VERSION 5.7 ;
  NOWIREEXTENSIONATPIN ON ;
  DIVIDERCHAR "/" ;
  BUSBITCHARS "[]" ;
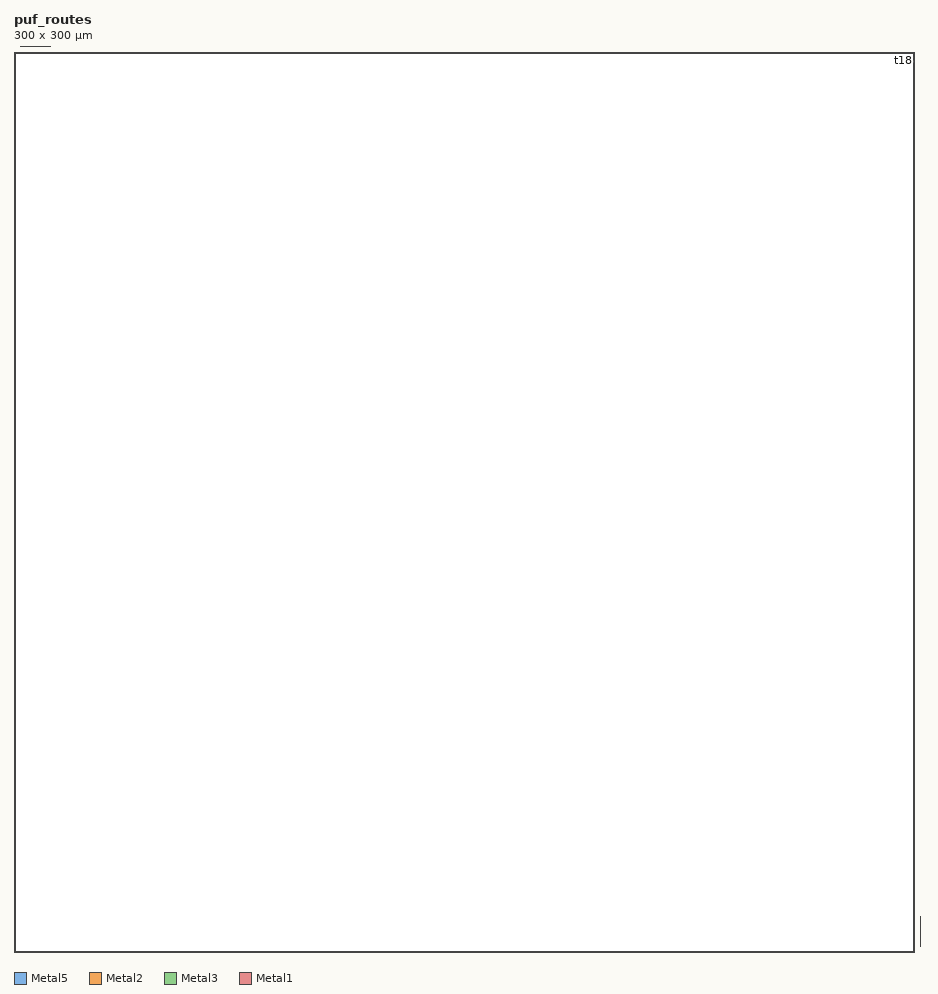
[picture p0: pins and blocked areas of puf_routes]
MACRO puf_routes
  CLASS BLOCK ;
  FOREIGN puf_routes ;
  ORIGIN 0.000 0.000 ;
  SIZE 300.000 BY 300.000 ;
  PIN HI
    DIRECTION INOUT ;
    USE ANALOG ;
    PORT
      LAYER Metal5 ;
        RECT 2.000 724.000 12.000 734.000 ;
      LAYER Metal2 ;
        RECT 330.000 706.860 335.000 751.140 ;
        RECT 331.730 728.130 333.470 729.870 ;
      LAYER Metal3 ;
        RECT 331.730 728.130 333.470 729.870 ;
      LAYER Metal2 ;
        RECT 331.000 728.000 334.000 730.000 ;
      LAYER Metal3 ;
        RECT 331.900 728.000 340.750 730.000 ;
      LAYER Metal1 ;
        RECT 338.700 727.200 342.300 730.800 ;
      LAYER Metal2 ;
        RECT 338.700 727.200 342.300 730.800 ;
        RECT 338.700 727.200 342.300 730.800 ;
      LAYER Metal3 ;
        RECT 338.700 727.200 342.300 730.800 ;
        RECT 338.500 1082.550 636.100 1086.550 ;
      LAYER Metal2 ;
        RECT 632.300 1082.750 635.900 1086.350 ;
      LAYER Metal3 ;
        RECT 632.300 1082.750 635.900 1086.350 ;
      LAYER Metal2 ;
        RECT 634.100 1082.550 637.100 1086.550 ;
      LAYER Metal3 ;
        RECT 338.500 1563.350 716.100 1567.350 ;
      LAYER Metal2 ;
        RECT 712.300 1563.550 715.900 1567.150 ;
      LAYER Metal3 ;
        RECT 712.300 1563.550 715.900 1567.150 ;
      LAYER Metal2 ;
        RECT 714.100 1563.350 717.100 1567.350 ;
      LAYER Metal1 ;
        RECT 338.500 338.500 342.500 1567.350 ;
        RECT 338.500 338.500 3507.500 342.500 ;
      LAYER Metal3 ;
        RECT 3227.900 649.550 3507.500 653.550 ;
      LAYER Metal2 ;
        RECT 3228.100 649.750 3231.700 653.350 ;
      LAYER Metal3 ;
        RECT 3228.100 649.750 3231.700 653.350 ;
      LAYER Metal2 ;
        RECT 3226.900 649.550 3229.900 653.550 ;
      LAYER Metal3 ;
        RECT 3177.900 1098.850 3507.500 1102.850 ;
      LAYER Metal2 ;
        RECT 3178.100 1099.050 3181.700 1102.650 ;
      LAYER Metal3 ;
        RECT 3178.100 1099.050 3181.700 1102.650 ;
      LAYER Metal2 ;
        RECT 3176.900 1098.850 3179.900 1102.850 ;
      LAYER Metal3 ;
        RECT 3237.900 1456.250 3507.500 1460.250 ;
      LAYER Metal2 ;
        RECT 3238.100 1456.450 3241.700 1460.050 ;
      LAYER Metal3 ;
        RECT 3238.100 1456.450 3241.700 1460.050 ;
      LAYER Metal2 ;
        RECT 3236.900 1456.250 3239.900 1460.250 ;
      LAYER Metal3 ;
        RECT 3137.900 1811.250 3507.500 1815.250 ;
      LAYER Metal2 ;
        RECT 3138.100 1811.450 3141.700 1815.050 ;
      LAYER Metal3 ;
        RECT 3138.100 1811.450 3141.700 1815.050 ;
      LAYER Metal2 ;
        RECT 3136.900 1811.250 3139.900 1815.250 ;
      LAYER Metal1 ;
        RECT 3503.500 338.500 3507.500 1815.250 ;
        RECT 338.700 1082.750 342.300 1086.350 ;
      LAYER Metal2 ;
        RECT 338.700 1082.750 342.300 1086.350 ;
        RECT 338.700 1082.750 342.300 1086.350 ;
      LAYER Metal3 ;
        RECT 338.700 1082.750 342.300 1086.350 ;
      LAYER Metal1 ;
        RECT 338.700 1563.550 342.300 1567.150 ;
      LAYER Metal2 ;
        RECT 338.700 1563.550 342.300 1567.150 ;
        RECT 338.700 1563.550 342.300 1567.150 ;
      LAYER Metal3 ;
        RECT 338.700 1563.550 342.300 1567.150 ;
      LAYER Metal1 ;
        RECT 3503.700 649.750 3507.300 653.350 ;
      LAYER Metal2 ;
        RECT 3503.700 649.750 3507.300 653.350 ;
        RECT 3503.700 649.750 3507.300 653.350 ;
      LAYER Metal3 ;
        RECT 3503.700 649.750 3507.300 653.350 ;
      LAYER Metal1 ;
        RECT 3503.700 1099.050 3507.300 1102.650 ;
      LAYER Metal2 ;
        RECT 3503.700 1099.050 3507.300 1102.650 ;
        RECT 3503.700 1099.050 3507.300 1102.650 ;
      LAYER Metal3 ;
        RECT 3503.700 1099.050 3507.300 1102.650 ;
      LAYER Metal1 ;
        RECT 3503.700 1456.450 3507.300 1460.050 ;
      LAYER Metal2 ;
        RECT 3503.700 1456.450 3507.300 1460.050 ;
        RECT 3503.700 1456.450 3507.300 1460.050 ;
      LAYER Metal3 ;
        RECT 3503.700 1456.450 3507.300 1460.050 ;
      LAYER Metal1 ;
        RECT 3503.700 1811.450 3507.300 1815.050 ;
      LAYER Metal2 ;
        RECT 3503.700 1811.450 3507.300 1815.050 ;
        RECT 3503.700 1811.450 3507.300 1815.050 ;
      LAYER Metal3 ;
        RECT 3503.700 1811.450 3507.300 1815.050 ;
    END
  END HI
  PIN LO
    DIRECTION INOUT ;
    USE ANALOG ;
    PORT
      LAYER Metal5 ;
        RECT 2.000 865.000 12.000 875.000 ;
      LAYER Metal2 ;
        RECT 330.000 847.860 335.000 892.140 ;
        RECT 331.730 869.130 333.470 870.870 ;
      LAYER Metal3 ;
        RECT 331.730 869.130 333.470 870.870 ;
      LAYER Metal2 ;
        RECT 331.000 869.000 334.000 871.000 ;
      LAYER Metal3 ;
        RECT 331.900 869.000 345.450 871.000 ;
      LAYER Metal1 ;
        RECT 343.400 868.200 347.000 871.800 ;
      LAYER Metal2 ;
        RECT 343.400 868.200 347.000 871.800 ;
        RECT 343.400 868.200 347.000 871.800 ;
      LAYER Metal3 ;
        RECT 343.400 868.200 347.000 871.800 ;
        RECT 343.200 1087.550 636.100 1091.550 ;
      LAYER Metal2 ;
        RECT 632.300 1087.750 635.900 1091.350 ;
      LAYER Metal3 ;
        RECT 632.300 1087.750 635.900 1091.350 ;
      LAYER Metal2 ;
        RECT 634.100 1087.550 637.100 1091.550 ;
      LAYER Metal3 ;
        RECT 343.200 1568.350 716.100 1572.350 ;
      LAYER Metal2 ;
        RECT 712.300 1568.550 715.900 1572.150 ;
      LAYER Metal3 ;
        RECT 712.300 1568.550 715.900 1572.150 ;
      LAYER Metal2 ;
        RECT 714.100 1568.350 717.100 1572.350 ;
      LAYER Metal1 ;
        RECT 343.200 343.200 347.200 1572.350 ;
        RECT 343.200 343.200 3502.800 347.200 ;
      LAYER Metal3 ;
        RECT 3227.900 654.550 3502.800 658.550 ;
      LAYER Metal2 ;
        RECT 3228.100 654.750 3231.700 658.350 ;
      LAYER Metal3 ;
        RECT 3228.100 654.750 3231.700 658.350 ;
      LAYER Metal2 ;
        RECT 3226.900 654.550 3229.900 658.550 ;
      LAYER Metal3 ;
        RECT 3177.900 1103.850 3502.800 1107.850 ;
      LAYER Metal2 ;
        RECT 3178.100 1104.050 3181.700 1107.650 ;
      LAYER Metal3 ;
        RECT 3178.100 1104.050 3181.700 1107.650 ;
      LAYER Metal2 ;
        RECT 3176.900 1103.850 3179.900 1107.850 ;
      LAYER Metal3 ;
        RECT 3237.900 1461.250 3502.800 1465.250 ;
      LAYER Metal2 ;
        RECT 3238.100 1461.450 3241.700 1465.050 ;
      LAYER Metal3 ;
        RECT 3238.100 1461.450 3241.700 1465.050 ;
      LAYER Metal2 ;
        RECT 3236.900 1461.250 3239.900 1465.250 ;
      LAYER Metal3 ;
        RECT 3432.000 1801.000 3502.800 1805.000 ;
      LAYER Metal2 ;
        RECT 3432.200 1801.200 3435.800 1804.800 ;
      LAYER Metal3 ;
        RECT 3432.200 1801.200 3435.800 1804.800 ;
      LAYER Metal2 ;
        RECT 3432.000 1801.000 3436.000 1820.250 ;
        RECT 3432.200 1816.450 3435.800 1820.050 ;
      LAYER Metal3 ;
        RECT 3432.200 1816.450 3435.800 1820.050 ;
        RECT 3137.900 1816.250 3436.000 1820.250 ;
      LAYER Metal2 ;
        RECT 3138.100 1816.450 3141.700 1820.050 ;
      LAYER Metal3 ;
        RECT 3138.100 1816.450 3141.700 1820.050 ;
      LAYER Metal2 ;
        RECT 3136.900 1816.250 3139.900 1820.250 ;
      LAYER Metal1 ;
        RECT 3498.800 343.200 3502.800 1805.000 ;
        RECT 343.400 1087.750 347.000 1091.350 ;
      LAYER Metal2 ;
        RECT 343.400 1087.750 347.000 1091.350 ;
        RECT 343.400 1087.750 347.000 1091.350 ;
      LAYER Metal3 ;
        RECT 343.400 1087.750 347.000 1091.350 ;
      LAYER Metal1 ;
        RECT 343.400 1568.550 347.000 1572.150 ;
      LAYER Metal2 ;
        RECT 343.400 1568.550 347.000 1572.150 ;
        RECT 343.400 1568.550 347.000 1572.150 ;
      LAYER Metal3 ;
        RECT 343.400 1568.550 347.000 1572.150 ;
      LAYER Metal1 ;
        RECT 3499.000 654.750 3502.600 658.350 ;
      LAYER Metal2 ;
        RECT 3499.000 654.750 3502.600 658.350 ;
        RECT 3499.000 654.750 3502.600 658.350 ;
      LAYER Metal3 ;
        RECT 3499.000 654.750 3502.600 658.350 ;
      LAYER Metal1 ;
        RECT 3499.000 1104.050 3502.600 1107.650 ;
      LAYER Metal2 ;
        RECT 3499.000 1104.050 3502.600 1107.650 ;
        RECT 3499.000 1104.050 3502.600 1107.650 ;
      LAYER Metal3 ;
        RECT 3499.000 1104.050 3502.600 1107.650 ;
      LAYER Metal1 ;
        RECT 3499.000 1461.450 3502.600 1465.050 ;
      LAYER Metal2 ;
        RECT 3499.000 1461.450 3502.600 1465.050 ;
        RECT 3499.000 1461.450 3502.600 1465.050 ;
      LAYER Metal3 ;
        RECT 3499.000 1461.450 3502.600 1465.050 ;
      LAYER Metal1 ;
        RECT 3499.000 1801.200 3502.600 1804.800 ;
      LAYER Metal2 ;
        RECT 3499.000 1801.200 3502.600 1804.800 ;
        RECT 3499.000 1801.200 3502.600 1804.800 ;
      LAYER Metal3 ;
        RECT 3499.000 1801.200 3502.600 1804.800 ;
    END
  END LO
  PIN t0
    DIRECTION INOUT ;
    USE ANALOG ;
    PORT
      LAYER Metal5 ;
        RECT 2.000 1006.000 12.000 1016.000 ;
      LAYER Metal2 ;
        RECT 330.000 988.860 335.000 1033.140 ;
        RECT 331.730 1010.130 333.470 1011.870 ;
      LAYER Metal3 ;
        RECT 331.730 1010.130 333.470 1011.870 ;
      LAYER Metal2 ;
        RECT 331.000 1010.000 334.000 1012.000 ;
      LAYER Metal3 ;
        RECT 331.900 1010.000 351.250 1012.000 ;
      LAYER Metal1 ;
        RECT 350.750 1010.750 351.250 1011.250 ;
      LAYER Metal2 ;
        RECT 350.750 1010.750 351.250 1011.250 ;
        RECT 350.750 1010.750 351.250 1011.250 ;
      LAYER Metal3 ;
        RECT 350.750 1010.750 351.250 1011.250 ;
      LAYER Metal1 ;
        RECT 350.650 1010.650 351.350 1094.000 ;
        RECT 350.750 1093.400 351.250 1093.900 ;
      LAYER Metal2 ;
        RECT 350.750 1093.400 351.250 1093.900 ;
        RECT 350.750 1093.400 351.250 1093.900 ;
      LAYER Metal3 ;
        RECT 350.750 1093.400 351.250 1093.900 ;
        RECT 350.700 1093.350 637.400 1093.950 ;
    END
  END t0
  PIN t1
    DIRECTION INOUT ;
    USE ANALOG ;
    PORT
      LAYER Metal5 ;
        RECT 2.000 1147.000 12.000 1157.000 ;
      LAYER Metal2 ;
        RECT 330.000 1129.860 335.000 1174.140 ;
        RECT 331.730 1151.130 333.470 1152.870 ;
      LAYER Metal3 ;
        RECT 331.730 1151.130 333.470 1152.870 ;
      LAYER Metal2 ;
        RECT 331.000 1151.000 334.000 1153.000 ;
      LAYER Metal3 ;
        RECT 331.900 1151.000 352.550 1153.000 ;
      LAYER Metal1 ;
        RECT 352.050 1151.750 352.550 1152.250 ;
      LAYER Metal2 ;
        RECT 352.050 1151.750 352.550 1152.250 ;
        RECT 352.050 1151.750 352.550 1152.250 ;
      LAYER Metal3 ;
        RECT 352.050 1151.750 352.550 1152.250 ;
      LAYER Metal1 ;
        RECT 351.950 1094.400 352.650 1152.350 ;
        RECT 352.050 1094.500 352.550 1095.000 ;
      LAYER Metal2 ;
        RECT 352.050 1094.500 352.550 1095.000 ;
        RECT 352.050 1094.500 352.550 1095.000 ;
      LAYER Metal3 ;
        RECT 352.050 1094.500 352.550 1095.000 ;
        RECT 352.000 1094.450 637.400 1095.050 ;
    END
  END t1
  PIN t2
    DIRECTION INOUT ;
    USE ANALOG ;
    PORT
      LAYER Metal5 ;
        RECT 2.000 1288.000 12.000 1298.000 ;
      LAYER Metal2 ;
        RECT 330.000 1270.860 335.000 1315.140 ;
        RECT 331.730 1292.130 333.470 1293.870 ;
      LAYER Metal3 ;
        RECT 331.730 1292.130 333.470 1293.870 ;
      LAYER Metal2 ;
        RECT 331.000 1292.000 334.000 1294.000 ;
      LAYER Metal3 ;
        RECT 331.900 1292.000 353.850 1294.000 ;
      LAYER Metal1 ;
        RECT 353.350 1292.750 353.850 1293.250 ;
      LAYER Metal2 ;
        RECT 353.350 1292.750 353.850 1293.250 ;
        RECT 353.350 1292.750 353.850 1293.250 ;
      LAYER Metal3 ;
        RECT 353.350 1292.750 353.850 1293.250 ;
      LAYER Metal1 ;
        RECT 353.250 1095.500 353.950 1293.350 ;
        RECT 353.350 1095.600 353.850 1096.100 ;
      LAYER Metal2 ;
        RECT 353.350 1095.600 353.850 1096.100 ;
        RECT 353.350 1095.600 353.850 1096.100 ;
      LAYER Metal3 ;
        RECT 353.350 1095.600 353.850 1096.100 ;
        RECT 353.300 1095.550 637.400 1096.150 ;
    END
  END t2
  PIN t3
    DIRECTION INOUT ;
    USE ANALOG ;
    PORT
      LAYER Metal5 ;
        RECT 2.000 1429.000 12.000 1439.000 ;
      LAYER Metal2 ;
        RECT 330.000 1411.860 335.000 1456.140 ;
        RECT 331.730 1433.130 333.470 1434.870 ;
      LAYER Metal3 ;
        RECT 331.730 1433.130 333.470 1434.870 ;
      LAYER Metal2 ;
        RECT 331.000 1433.000 334.000 1435.000 ;
      LAYER Metal3 ;
        RECT 331.900 1433.000 355.150 1435.000 ;
      LAYER Metal1 ;
        RECT 354.650 1433.750 355.150 1434.250 ;
      LAYER Metal2 ;
        RECT 354.650 1433.750 355.150 1434.250 ;
        RECT 354.650 1433.750 355.150 1434.250 ;
      LAYER Metal3 ;
        RECT 354.650 1433.750 355.150 1434.250 ;
      LAYER Metal1 ;
        RECT 354.550 1096.600 355.250 1434.350 ;
        RECT 354.650 1096.700 355.150 1097.200 ;
      LAYER Metal2 ;
        RECT 354.650 1096.700 355.150 1097.200 ;
        RECT 354.650 1096.700 355.150 1097.200 ;
      LAYER Metal3 ;
        RECT 354.650 1096.700 355.150 1097.200 ;
        RECT 354.600 1096.650 637.400 1097.250 ;
    END
  END t3
  PIN t4
    DIRECTION INOUT ;
    USE ANALOG ;
    PORT
      LAYER Metal5 ;
        RECT 2.000 1570.000 12.000 1580.000 ;
      LAYER Metal2 ;
        RECT 330.000 1552.860 335.000 1597.140 ;
        RECT 331.730 1574.130 333.470 1575.870 ;
      LAYER Metal3 ;
        RECT 331.730 1574.130 333.470 1575.870 ;
      LAYER Metal2 ;
        RECT 331.000 1574.000 334.000 1576.000 ;
      LAYER Metal3 ;
        RECT 331.900 1574.000 356.450 1576.000 ;
        RECT 355.900 1574.150 717.400 1574.750 ;
    END
  END t4
  PIN t5
    DIRECTION INOUT ;
    USE ANALOG ;
    PORT
      LAYER Metal5 ;
        RECT 2.000 1711.000 12.000 1721.000 ;
      LAYER Metal2 ;
        RECT 330.000 1693.860 335.000 1738.140 ;
        RECT 331.730 1715.130 333.470 1716.870 ;
      LAYER Metal3 ;
        RECT 331.730 1715.130 333.470 1716.870 ;
      LAYER Metal2 ;
        RECT 331.000 1715.000 334.000 1717.000 ;
      LAYER Metal3 ;
        RECT 331.900 1715.000 357.750 1717.000 ;
      LAYER Metal1 ;
        RECT 357.250 1715.750 357.750 1716.250 ;
      LAYER Metal2 ;
        RECT 357.250 1715.750 357.750 1716.250 ;
        RECT 357.250 1715.750 357.750 1716.250 ;
      LAYER Metal3 ;
        RECT 357.250 1715.750 357.750 1716.250 ;
      LAYER Metal1 ;
        RECT 357.150 1575.200 357.850 1716.350 ;
        RECT 357.250 1575.300 357.750 1575.800 ;
      LAYER Metal2 ;
        RECT 357.250 1575.300 357.750 1575.800 ;
        RECT 357.250 1575.300 357.750 1575.800 ;
      LAYER Metal3 ;
        RECT 357.250 1575.300 357.750 1575.800 ;
        RECT 357.200 1575.250 717.400 1575.850 ;
    END
  END t5
  PIN t6
    DIRECTION INOUT ;
    USE ANALOG ;
    PORT
      LAYER Metal5 ;
        RECT 1466.500 2.000 1476.500 12.000 ;
      LAYER Metal2 ;
        RECT 1449.360 330.000 1493.640 335.000 ;
        RECT 1470.500 330.000 1472.500 352.000 ;
      LAYER Metal1 ;
        RECT 1471.250 350.750 1471.750 351.250 ;
      LAYER Metal2 ;
        RECT 1471.250 350.750 1471.750 351.250 ;
      LAYER Metal1 ;
        RECT 358.450 350.650 1471.850 351.350 ;
        RECT 358.450 350.650 359.150 1098.400 ;
        RECT 358.550 1097.800 359.050 1098.300 ;
      LAYER Metal2 ;
        RECT 358.550 1097.800 359.050 1098.300 ;
        RECT 358.550 1097.800 359.050 1098.300 ;
      LAYER Metal3 ;
        RECT 358.550 1097.800 359.050 1098.300 ;
        RECT 358.500 1097.750 637.400 1098.350 ;
    END
  END t6
  PIN t7
    DIRECTION INOUT ;
    USE ANALOG ;
    PORT
      LAYER Metal5 ;
        RECT 1595.500 2.000 1605.500 12.000 ;
      LAYER Metal2 ;
        RECT 1578.360 330.000 1622.640 335.000 ;
        RECT 1599.500 330.000 1601.500 353.300 ;
      LAYER Metal1 ;
        RECT 1600.250 352.050 1600.750 352.550 ;
      LAYER Metal2 ;
        RECT 1600.250 352.050 1600.750 352.550 ;
      LAYER Metal1 ;
        RECT 359.750 351.950 1600.850 352.650 ;
        RECT 359.750 351.950 360.450 1099.500 ;
        RECT 359.850 1098.900 360.350 1099.400 ;
      LAYER Metal2 ;
        RECT 359.850 1098.900 360.350 1099.400 ;
        RECT 359.850 1098.900 360.350 1099.400 ;
      LAYER Metal3 ;
        RECT 359.850 1098.900 360.350 1099.400 ;
        RECT 359.800 1098.850 637.400 1099.450 ;
    END
  END t7
  PIN t8
    DIRECTION INOUT ;
    USE ANALOG ;
    PORT
      LAYER Metal5 ;
        RECT 1724.500 2.000 1734.500 12.000 ;
      LAYER Metal2 ;
        RECT 1707.360 330.000 1751.640 335.000 ;
        RECT 1728.500 330.000 1730.500 354.600 ;
      LAYER Metal1 ;
        RECT 1729.250 353.350 1729.750 353.850 ;
      LAYER Metal2 ;
        RECT 1729.250 353.350 1729.750 353.850 ;
      LAYER Metal1 ;
        RECT 361.050 353.250 1729.850 353.950 ;
        RECT 361.050 353.250 361.750 1100.600 ;
        RECT 361.150 1100.000 361.650 1100.500 ;
      LAYER Metal2 ;
        RECT 361.150 1100.000 361.650 1100.500 ;
        RECT 361.150 1100.000 361.650 1100.500 ;
      LAYER Metal3 ;
        RECT 361.150 1100.000 361.650 1100.500 ;
        RECT 361.100 1099.950 637.400 1100.550 ;
    END
  END t8
  PIN t9
    DIRECTION INOUT ;
    USE ANALOG ;
    PORT
      LAYER Metal5 ;
        RECT 1853.500 2.000 1863.500 12.000 ;
      LAYER Metal2 ;
        RECT 1836.360 330.000 1880.640 335.000 ;
        RECT 1857.500 330.000 1859.500 355.900 ;
      LAYER Metal1 ;
        RECT 1858.250 354.650 1858.750 355.150 ;
      LAYER Metal2 ;
        RECT 1858.250 354.650 1858.750 355.150 ;
      LAYER Metal1 ;
        RECT 362.350 354.550 1858.850 355.250 ;
        RECT 362.350 354.550 363.050 1101.700 ;
        RECT 362.450 1101.100 362.950 1101.600 ;
      LAYER Metal2 ;
        RECT 362.450 1101.100 362.950 1101.600 ;
        RECT 362.450 1101.100 362.950 1101.600 ;
      LAYER Metal3 ;
        RECT 362.450 1101.100 362.950 1101.600 ;
        RECT 362.400 1101.050 637.400 1101.650 ;
    END
  END t9
  PIN t10
    DIRECTION INOUT ;
    USE ANALOG ;
    PORT
      LAYER Metal5 ;
        RECT 1982.500 2.000 1992.500 12.000 ;
      LAYER Metal2 ;
        RECT 1965.360 330.000 2009.640 335.000 ;
        RECT 1986.500 330.000 1988.500 357.200 ;
      LAYER Metal1 ;
        RECT 1987.250 355.950 1987.750 356.450 ;
      LAYER Metal2 ;
        RECT 1987.250 355.950 1987.750 356.450 ;
      LAYER Metal1 ;
        RECT 363.650 355.850 1987.850 356.550 ;
        RECT 363.650 355.850 364.350 1577.000 ;
        RECT 363.750 1576.400 364.250 1576.900 ;
      LAYER Metal2 ;
        RECT 363.750 1576.400 364.250 1576.900 ;
        RECT 363.750 1576.400 364.250 1576.900 ;
      LAYER Metal3 ;
        RECT 363.750 1576.400 364.250 1576.900 ;
        RECT 363.700 1576.350 717.400 1576.950 ;
    END
  END t10
  PIN t11
    DIRECTION INOUT ;
    USE ANALOG ;
    PORT
      LAYER Metal5 ;
        RECT 2111.500 2.000 2121.500 12.000 ;
      LAYER Metal2 ;
        RECT 2094.360 330.000 2138.640 335.000 ;
        RECT 2115.500 330.000 2117.500 358.500 ;
      LAYER Metal1 ;
        RECT 2116.250 357.250 2116.750 357.750 ;
      LAYER Metal2 ;
        RECT 2116.250 357.250 2116.750 357.750 ;
      LAYER Metal1 ;
        RECT 364.950 357.150 2116.850 357.850 ;
        RECT 364.950 357.150 365.650 1578.100 ;
        RECT 365.050 1577.500 365.550 1578.000 ;
      LAYER Metal2 ;
        RECT 365.050 1577.500 365.550 1578.000 ;
        RECT 365.050 1577.500 365.550 1578.000 ;
      LAYER Metal3 ;
        RECT 365.050 1577.500 365.550 1578.000 ;
        RECT 365.000 1577.450 717.400 1578.050 ;
    END
  END t11
  PIN t12
    DIRECTION INOUT ;
    USE ANALOG ;
    PORT
      LAYER Metal5 ;
        RECT 2240.500 2.000 2250.500 12.000 ;
      LAYER Metal2 ;
        RECT 2223.360 330.000 2267.640 335.000 ;
        RECT 2244.500 330.000 2246.500 359.800 ;
      LAYER Metal1 ;
        RECT 2245.250 358.550 2245.750 359.050 ;
      LAYER Metal2 ;
        RECT 2245.250 358.550 2245.750 359.050 ;
      LAYER Metal1 ;
        RECT 366.250 358.450 2245.850 359.150 ;
        RECT 366.250 358.450 366.950 1579.200 ;
        RECT 366.350 1578.600 366.850 1579.100 ;
      LAYER Metal2 ;
        RECT 366.350 1578.600 366.850 1579.100 ;
        RECT 366.350 1578.600 366.850 1579.100 ;
      LAYER Metal3 ;
        RECT 366.350 1578.600 366.850 1579.100 ;
        RECT 366.300 1578.550 717.400 1579.150 ;
    END
  END t12
  PIN t13
    DIRECTION INOUT ;
    USE ANALOG ;
    PORT
      LAYER Metal5 ;
        RECT 2369.500 2.000 2379.500 12.000 ;
      LAYER Metal2 ;
        RECT 2352.360 330.000 2396.640 335.000 ;
        RECT 2373.500 330.000 2375.500 361.100 ;
      LAYER Metal1 ;
        RECT 2374.250 359.850 2374.750 360.350 ;
      LAYER Metal2 ;
        RECT 2374.250 359.850 2374.750 360.350 ;
      LAYER Metal1 ;
        RECT 367.550 359.750 2374.850 360.450 ;
        RECT 367.550 359.750 368.250 1580.300 ;
        RECT 367.650 1579.700 368.150 1580.200 ;
      LAYER Metal2 ;
        RECT 367.650 1579.700 368.150 1580.200 ;
        RECT 367.650 1579.700 368.150 1580.200 ;
      LAYER Metal3 ;
        RECT 367.650 1579.700 368.150 1580.200 ;
        RECT 367.600 1579.650 717.400 1580.250 ;
    END
  END t13
  PIN t14
    DIRECTION INOUT ;
    USE ANALOG ;
    PORT
      LAYER Metal5 ;
        RECT 2498.500 2.000 2508.500 12.000 ;
      LAYER Metal2 ;
        RECT 2481.360 330.000 2525.640 335.000 ;
        RECT 2502.500 330.000 2504.500 362.400 ;
      LAYER Metal1 ;
        RECT 2503.250 361.150 2503.750 361.650 ;
      LAYER Metal2 ;
        RECT 2503.250 361.150 2503.750 361.650 ;
      LAYER Metal1 ;
        RECT 368.850 361.050 2503.850 361.750 ;
        RECT 368.850 361.050 369.550 1581.400 ;
        RECT 368.950 1580.800 369.450 1581.300 ;
      LAYER Metal2 ;
        RECT 368.950 1580.800 369.450 1581.300 ;
        RECT 368.950 1580.800 369.450 1581.300 ;
      LAYER Metal3 ;
        RECT 368.950 1580.800 369.450 1581.300 ;
        RECT 368.900 1580.750 717.400 1581.350 ;
    END
  END t14
  PIN t15
    DIRECTION INOUT ;
    USE ANALOG ;
    PORT
      LAYER Metal5 ;
        RECT 2627.500 2.000 2637.500 12.000 ;
      LAYER Metal2 ;
        RECT 2610.360 330.000 2654.640 335.000 ;
        RECT 2631.500 330.000 2633.500 363.700 ;
      LAYER Metal1 ;
        RECT 2632.250 362.450 2632.750 362.950 ;
      LAYER Metal2 ;
        RECT 2632.250 362.450 2632.750 362.950 ;
      LAYER Metal1 ;
        RECT 370.150 362.350 2632.850 363.050 ;
        RECT 370.150 362.350 370.850 1582.500 ;
        RECT 370.250 1581.900 370.750 1582.400 ;
      LAYER Metal2 ;
        RECT 370.250 1581.900 370.750 1582.400 ;
        RECT 370.250 1581.900 370.750 1582.400 ;
      LAYER Metal3 ;
        RECT 370.250 1581.900 370.750 1582.400 ;
        RECT 370.200 1581.850 717.400 1582.450 ;
    END
  END t15
  PIN t16
    DIRECTION INOUT ;
    USE ANALOG ;
    PORT
      LAYER Metal5 ;
        RECT 3014.500 2.000 3024.500 12.000 ;
      LAYER Metal2 ;
        RECT 2997.360 330.000 3041.640 335.000 ;
        RECT 3018.500 330.000 3020.500 365.000 ;
      LAYER Metal1 ;
        RECT 3019.250 363.750 3019.750 364.250 ;
      LAYER Metal2 ;
        RECT 3019.250 363.750 3019.750 364.250 ;
      LAYER Metal1 ;
        RECT 3019.150 363.650 3495.350 364.350 ;
        RECT 3494.650 363.650 3495.350 661.000 ;
        RECT 3494.750 660.400 3495.250 660.900 ;
      LAYER Metal2 ;
        RECT 3494.750 660.400 3495.250 660.900 ;
        RECT 3494.750 660.400 3495.250 660.900 ;
      LAYER Metal3 ;
        RECT 3494.750 660.400 3495.250 660.900 ;
        RECT 3226.600 660.350 3495.300 660.950 ;
    END
  END t16
  PIN t17
    DIRECTION INOUT ;
    USE ANALOG ;
    PORT
      LAYER Metal5 ;
        RECT 3143.500 2.000 3153.500 12.000 ;
      LAYER Metal2 ;
        RECT 3126.360 330.000 3170.640 335.000 ;
        RECT 3147.500 330.000 3149.500 366.300 ;
      LAYER Metal1 ;
        RECT 3148.250 365.050 3148.750 365.550 ;
      LAYER Metal2 ;
        RECT 3148.250 365.050 3148.750 365.550 ;
      LAYER Metal1 ;
        RECT 3148.150 364.950 3494.050 365.650 ;
        RECT 3493.350 364.950 3494.050 662.100 ;
        RECT 3493.450 661.500 3493.950 662.000 ;
      LAYER Metal2 ;
        RECT 3493.450 661.500 3493.950 662.000 ;
        RECT 3493.450 661.500 3493.950 662.000 ;
      LAYER Metal3 ;
        RECT 3493.450 661.500 3493.950 662.000 ;
        RECT 3226.600 661.450 3494.000 662.050 ;
    END
  END t17
  PIN t18
    DIRECTION INOUT ;
    USE ANALOG ;
    PORT
      LAYER Metal5 ;
        RECT 3272.500 2.000 3282.500 12.000 ;
      LAYER Metal2 ;
        RECT 3255.360 330.000 3299.640 335.000 ;
        RECT 3276.500 330.000 3278.500 367.600 ;
      LAYER Metal1 ;
        RECT 3277.250 366.350 3277.750 366.850 ;
      LAYER Metal2 ;
        RECT 3277.250 366.350 3277.750 366.850 ;
      LAYER Metal1 ;
        RECT 3277.150 366.250 3492.750 366.950 ;
        RECT 3492.050 366.250 3492.750 663.200 ;
        RECT 3492.150 662.600 3492.650 663.100 ;
      LAYER Metal2 ;
        RECT 3492.150 662.600 3492.650 663.100 ;
        RECT 3492.150 662.600 3492.650 663.100 ;
      LAYER Metal3 ;
        RECT 3492.150 662.600 3492.650 663.100 ;
        RECT 3226.600 662.550 3492.700 663.150 ;
    END
  END t18
  PIN t19
    DIRECTION INOUT ;
    USE ANALOG ;
    PORT
      LAYER Metal5 ;
        RECT 3401.500 2.000 3411.500 12.000 ;
      LAYER Metal2 ;
        RECT 3384.360 330.000 3428.640 335.000 ;
        RECT 3405.500 330.000 3407.500 368.900 ;
      LAYER Metal1 ;
        RECT 3406.250 367.650 3406.750 368.150 ;
      LAYER Metal2 ;
        RECT 3406.250 367.650 3406.750 368.150 ;
      LAYER Metal1 ;
        RECT 3406.150 367.550 3491.450 368.250 ;
        RECT 3490.750 367.550 3491.450 664.300 ;
        RECT 3490.850 663.700 3491.350 664.200 ;
      LAYER Metal2 ;
        RECT 3490.850 663.700 3491.350 664.200 ;
        RECT 3490.850 663.700 3491.350 664.200 ;
      LAYER Metal3 ;
        RECT 3490.850 663.700 3491.350 664.200 ;
        RECT 3226.600 663.650 3491.400 664.250 ;
    END
  END t19
  PIN t20
    DIRECTION INOUT ;
    USE ANALOG ;
    PORT
      LAYER Metal5 ;
        RECT 3834.000 724.000 3844.000 734.000 ;
      LAYER Metal2 ;
        RECT 3511.000 706.860 3516.000 751.140 ;
        RECT 3512.530 728.130 3514.270 729.870 ;
      LAYER Metal3 ;
        RECT 3512.530 728.130 3514.270 729.870 ;
      LAYER Metal2 ;
        RECT 3512.000 728.000 3515.000 730.000 ;
      LAYER Metal3 ;
        RECT 3489.550 728.000 3514.100 730.000 ;
      LAYER Metal1 ;
        RECT 3489.550 728.750 3490.050 729.250 ;
      LAYER Metal2 ;
        RECT 3489.550 728.750 3490.050 729.250 ;
        RECT 3489.550 728.750 3490.050 729.250 ;
      LAYER Metal3 ;
        RECT 3489.550 728.750 3490.050 729.250 ;
      LAYER Metal1 ;
        RECT 3489.450 664.700 3490.150 729.350 ;
        RECT 3489.550 664.800 3490.050 665.300 ;
      LAYER Metal2 ;
        RECT 3489.550 664.800 3490.050 665.300 ;
        RECT 3489.550 664.800 3490.050 665.300 ;
      LAYER Metal3 ;
        RECT 3489.550 664.800 3490.050 665.300 ;
        RECT 3226.600 664.750 3490.100 665.350 ;
    END
  END t20
  PIN t21
    DIRECTION INOUT ;
    USE ANALOG ;
    PORT
      LAYER Metal5 ;
        RECT 3834.000 865.000 3844.000 875.000 ;
      LAYER Metal2 ;
        RECT 3511.000 847.860 3516.000 892.140 ;
        RECT 3512.530 869.130 3514.270 870.870 ;
      LAYER Metal3 ;
        RECT 3512.530 869.130 3514.270 870.870 ;
      LAYER Metal2 ;
        RECT 3512.000 869.000 3515.000 871.000 ;
      LAYER Metal3 ;
        RECT 3488.250 869.000 3514.100 871.000 ;
      LAYER Metal1 ;
        RECT 3488.250 869.750 3488.750 870.250 ;
      LAYER Metal2 ;
        RECT 3488.250 869.750 3488.750 870.250 ;
        RECT 3488.250 869.750 3488.750 870.250 ;
      LAYER Metal3 ;
        RECT 3488.250 869.750 3488.750 870.250 ;
      LAYER Metal1 ;
        RECT 3488.150 665.800 3488.850 870.350 ;
        RECT 3488.250 665.900 3488.750 666.400 ;
      LAYER Metal2 ;
        RECT 3488.250 665.900 3488.750 666.400 ;
        RECT 3488.250 665.900 3488.750 666.400 ;
      LAYER Metal3 ;
        RECT 3488.250 665.900 3488.750 666.400 ;
        RECT 3226.600 665.850 3488.800 666.450 ;
    END
  END t21
  PIN t22
    DIRECTION INOUT ;
    USE ANALOG ;
    PORT
      LAYER Metal5 ;
        RECT 3834.000 1006.000 3844.000 1016.000 ;
      LAYER Metal2 ;
        RECT 3511.000 988.860 3516.000 1033.140 ;
        RECT 3512.530 1010.130 3514.270 1011.870 ;
      LAYER Metal3 ;
        RECT 3512.530 1010.130 3514.270 1011.870 ;
      LAYER Metal2 ;
        RECT 3512.000 1010.000 3515.000 1012.000 ;
      LAYER Metal3 ;
        RECT 3486.950 1010.000 3514.100 1012.000 ;
      LAYER Metal1 ;
        RECT 3486.950 1010.750 3487.450 1011.250 ;
      LAYER Metal2 ;
        RECT 3486.950 1010.750 3487.450 1011.250 ;
        RECT 3486.950 1010.750 3487.450 1011.250 ;
      LAYER Metal3 ;
        RECT 3486.950 1010.750 3487.450 1011.250 ;
      LAYER Metal1 ;
        RECT 3486.850 666.900 3487.550 1011.350 ;
        RECT 3486.950 667.000 3487.450 667.500 ;
      LAYER Metal2 ;
        RECT 3486.950 667.000 3487.450 667.500 ;
        RECT 3486.950 667.000 3487.450 667.500 ;
      LAYER Metal3 ;
        RECT 3486.950 667.000 3487.450 667.500 ;
        RECT 3226.600 666.950 3487.500 667.550 ;
    END
  END t22
  PIN t23
    DIRECTION INOUT ;
    USE ANALOG ;
    PORT
      LAYER Metal5 ;
        RECT 3834.000 1147.000 3844.000 1157.000 ;
      LAYER Metal2 ;
        RECT 3511.000 1129.860 3516.000 1174.140 ;
        RECT 3512.530 1151.130 3514.270 1152.870 ;
      LAYER Metal3 ;
        RECT 3512.530 1151.130 3514.270 1152.870 ;
      LAYER Metal2 ;
        RECT 3512.000 1151.000 3515.000 1153.000 ;
      LAYER Metal3 ;
        RECT 3485.650 1151.000 3514.100 1153.000 ;
      LAYER Metal1 ;
        RECT 3485.650 1151.750 3486.150 1152.250 ;
      LAYER Metal2 ;
        RECT 3485.650 1151.750 3486.150 1152.250 ;
        RECT 3485.650 1151.750 3486.150 1152.250 ;
      LAYER Metal3 ;
        RECT 3485.650 1151.750 3486.150 1152.250 ;
      LAYER Metal1 ;
        RECT 3485.550 668.000 3486.250 1152.350 ;
        RECT 3485.650 668.100 3486.150 668.600 ;
      LAYER Metal2 ;
        RECT 3485.650 668.100 3486.150 668.600 ;
        RECT 3485.650 668.100 3486.150 668.600 ;
      LAYER Metal3 ;
        RECT 3485.650 668.100 3486.150 668.600 ;
        RECT 3226.600 668.050 3486.200 668.650 ;
    END
  END t23
  PIN t24
    DIRECTION INOUT ;
    USE ANALOG ;
    PORT
      LAYER Metal5 ;
        RECT 3834.000 1288.000 3844.000 1298.000 ;
      LAYER Metal2 ;
        RECT 3511.000 1270.860 3516.000 1315.140 ;
        RECT 3512.530 1292.130 3514.270 1293.870 ;
      LAYER Metal3 ;
        RECT 3512.530 1292.130 3514.270 1293.870 ;
      LAYER Metal2 ;
        RECT 3512.000 1292.000 3515.000 1294.000 ;
      LAYER Metal3 ;
        RECT 3484.350 1292.000 3514.100 1294.000 ;
      LAYER Metal1 ;
        RECT 3484.350 1292.750 3484.850 1293.250 ;
      LAYER Metal2 ;
        RECT 3484.350 1292.750 3484.850 1293.250 ;
        RECT 3484.350 1292.750 3484.850 1293.250 ;
      LAYER Metal3 ;
        RECT 3484.350 1292.750 3484.850 1293.250 ;
      LAYER Metal1 ;
        RECT 3484.250 1292.650 3484.950 1467.700 ;
        RECT 3484.350 1467.100 3484.850 1467.600 ;
      LAYER Metal2 ;
        RECT 3484.350 1467.100 3484.850 1467.600 ;
        RECT 3484.350 1467.100 3484.850 1467.600 ;
      LAYER Metal3 ;
        RECT 3484.350 1467.100 3484.850 1467.600 ;
        RECT 3236.600 1467.050 3484.900 1467.650 ;
    END
  END t24
  PIN t25
    DIRECTION INOUT ;
    USE ANALOG ;
    PORT
      LAYER Metal5 ;
        RECT 3834.000 1429.000 3844.000 1439.000 ;
      LAYER Metal2 ;
        RECT 3511.000 1411.860 3516.000 1456.140 ;
        RECT 3512.530 1433.130 3514.270 1434.870 ;
      LAYER Metal3 ;
        RECT 3512.530 1433.130 3514.270 1434.870 ;
      LAYER Metal2 ;
        RECT 3512.000 1433.000 3515.000 1435.000 ;
      LAYER Metal3 ;
        RECT 3483.050 1433.000 3514.100 1435.000 ;
      LAYER Metal1 ;
        RECT 3483.050 1433.750 3483.550 1434.250 ;
      LAYER Metal2 ;
        RECT 3483.050 1433.750 3483.550 1434.250 ;
        RECT 3483.050 1433.750 3483.550 1434.250 ;
      LAYER Metal3 ;
        RECT 3483.050 1433.750 3483.550 1434.250 ;
      LAYER Metal1 ;
        RECT 3482.950 1433.650 3483.650 1468.800 ;
        RECT 3483.050 1468.200 3483.550 1468.700 ;
      LAYER Metal2 ;
        RECT 3483.050 1468.200 3483.550 1468.700 ;
        RECT 3483.050 1468.200 3483.550 1468.700 ;
      LAYER Metal3 ;
        RECT 3483.050 1468.200 3483.550 1468.700 ;
        RECT 3236.600 1468.150 3483.600 1468.750 ;
    END
  END t25
  PIN t26
    DIRECTION INOUT ;
    USE ANALOG ;
    PORT
      LAYER Metal5 ;
        RECT 3834.000 1570.000 3844.000 1580.000 ;
      LAYER Metal2 ;
        RECT 3511.000 1552.860 3516.000 1597.140 ;
        RECT 3512.530 1574.130 3514.270 1575.870 ;
      LAYER Metal3 ;
        RECT 3512.530 1574.130 3514.270 1575.870 ;
      LAYER Metal2 ;
        RECT 3512.000 1574.000 3515.000 1576.000 ;
      LAYER Metal3 ;
        RECT 3481.750 1574.000 3514.100 1576.000 ;
      LAYER Metal1 ;
        RECT 3481.750 1574.750 3482.250 1575.250 ;
      LAYER Metal2 ;
        RECT 3481.750 1574.750 3482.250 1575.250 ;
        RECT 3481.750 1574.750 3482.250 1575.250 ;
      LAYER Metal3 ;
        RECT 3481.750 1574.750 3482.250 1575.250 ;
      LAYER Metal1 ;
        RECT 3481.650 1469.200 3482.350 1575.350 ;
        RECT 3481.750 1469.300 3482.250 1469.800 ;
      LAYER Metal2 ;
        RECT 3481.750 1469.300 3482.250 1469.800 ;
        RECT 3481.750 1469.300 3482.250 1469.800 ;
      LAYER Metal3 ;
        RECT 3481.750 1469.300 3482.250 1469.800 ;
        RECT 3236.600 1469.250 3482.300 1469.850 ;
    END
  END t26
  PIN t27
    DIRECTION INOUT ;
    USE ANALOG ;
    PORT
      LAYER Metal5 ;
        RECT 3834.000 1711.000 3844.000 1721.000 ;
      LAYER Metal2 ;
        RECT 3511.000 1693.860 3516.000 1738.140 ;
        RECT 3512.530 1715.130 3514.270 1716.870 ;
      LAYER Metal3 ;
        RECT 3512.530 1715.130 3514.270 1716.870 ;
      LAYER Metal2 ;
        RECT 3512.000 1715.000 3515.000 1717.000 ;
      LAYER Metal3 ;
        RECT 3480.450 1715.000 3514.100 1717.000 ;
      LAYER Metal1 ;
        RECT 3480.450 1715.750 3480.950 1716.250 ;
      LAYER Metal2 ;
        RECT 3480.450 1715.750 3480.950 1716.250 ;
        RECT 3480.450 1715.750 3480.950 1716.250 ;
      LAYER Metal3 ;
        RECT 3480.450 1715.750 3480.950 1716.250 ;
      LAYER Metal1 ;
        RECT 3480.350 1470.300 3481.050 1716.350 ;
        RECT 3480.450 1470.400 3480.950 1470.900 ;
      LAYER Metal2 ;
        RECT 3480.450 1470.400 3480.950 1470.900 ;
        RECT 3480.450 1470.400 3480.950 1470.900 ;
      LAYER Metal3 ;
        RECT 3480.450 1470.400 3480.950 1470.900 ;
        RECT 3236.600 1470.350 3481.000 1470.950 ;
    END
  END t27
  PIN t28
    DIRECTION INOUT ;
    USE ANALOG ;
    PORT
      LAYER Metal5 ;
        RECT 434.500 2433.000 444.500 2443.000 ;
      LAYER Metal2 ;
        RECT 417.360 2110.000 461.640 2115.000 ;
        RECT 438.500 2099.800 440.500 2115.000 ;
      LAYER Metal1 ;
        RECT 439.250 2100.550 439.750 2101.050 ;
      LAYER Metal2 ;
        RECT 439.250 2100.550 439.750 2101.050 ;
      LAYER Metal1 ;
        RECT 439.150 2100.450 3464.150 2101.150 ;
        RECT 3463.450 1109.600 3464.150 2101.150 ;
        RECT 3463.550 1109.700 3464.050 1110.200 ;
      LAYER Metal2 ;
        RECT 3463.550 1109.700 3464.050 1110.200 ;
        RECT 3463.550 1109.700 3464.050 1110.200 ;
      LAYER Metal3 ;
        RECT 3463.550 1109.700 3464.050 1110.200 ;
        RECT 3176.600 1109.650 3464.100 1110.250 ;
    END
  END t28
  PIN t29
    DIRECTION INOUT ;
    USE ANALOG ;
    PORT
      LAYER Metal5 ;
        RECT 563.500 2433.000 573.500 2443.000 ;
      LAYER Metal2 ;
        RECT 546.360 2110.000 590.640 2115.000 ;
        RECT 567.500 2098.500 569.500 2115.000 ;
      LAYER Metal1 ;
        RECT 568.250 2099.250 568.750 2099.750 ;
      LAYER Metal2 ;
        RECT 568.250 2099.250 568.750 2099.750 ;
      LAYER Metal1 ;
        RECT 568.150 2099.150 3462.850 2099.850 ;
        RECT 3462.150 1110.700 3462.850 2099.850 ;
        RECT 3462.250 1110.800 3462.750 1111.300 ;
      LAYER Metal2 ;
        RECT 3462.250 1110.800 3462.750 1111.300 ;
        RECT 3462.250 1110.800 3462.750 1111.300 ;
      LAYER Metal3 ;
        RECT 3462.250 1110.800 3462.750 1111.300 ;
        RECT 3176.600 1110.750 3462.800 1111.350 ;
    END
  END t29
  PIN t30
    DIRECTION INOUT ;
    USE ANALOG ;
    PORT
      LAYER Metal5 ;
        RECT 692.500 2433.000 702.500 2443.000 ;
      LAYER Metal2 ;
        RECT 675.360 2110.000 719.640 2115.000 ;
        RECT 696.500 2097.200 698.500 2115.000 ;
      LAYER Metal1 ;
        RECT 697.250 2097.950 697.750 2098.450 ;
      LAYER Metal2 ;
        RECT 697.250 2097.950 697.750 2098.450 ;
      LAYER Metal1 ;
        RECT 697.150 2097.850 3461.550 2098.550 ;
        RECT 3460.850 1111.800 3461.550 2098.550 ;
        RECT 3460.950 1111.900 3461.450 1112.400 ;
      LAYER Metal2 ;
        RECT 3460.950 1111.900 3461.450 1112.400 ;
        RECT 3460.950 1111.900 3461.450 1112.400 ;
      LAYER Metal3 ;
        RECT 3460.950 1111.900 3461.450 1112.400 ;
        RECT 3176.600 1111.850 3461.500 1112.450 ;
    END
  END t30
  PIN t31
    DIRECTION INOUT ;
    USE ANALOG ;
    PORT
      LAYER Metal5 ;
        RECT 821.500 2433.000 831.500 2443.000 ;
      LAYER Metal2 ;
        RECT 804.360 2110.000 848.640 2115.000 ;
        RECT 825.500 2095.900 827.500 2115.000 ;
      LAYER Metal1 ;
        RECT 826.250 2096.650 826.750 2097.150 ;
      LAYER Metal2 ;
        RECT 826.250 2096.650 826.750 2097.150 ;
      LAYER Metal1 ;
        RECT 826.150 2096.550 3460.250 2097.250 ;
        RECT 3459.550 1112.900 3460.250 2097.250 ;
        RECT 3459.650 1113.000 3460.150 1113.500 ;
      LAYER Metal2 ;
        RECT 3459.650 1113.000 3460.150 1113.500 ;
        RECT 3459.650 1113.000 3460.150 1113.500 ;
      LAYER Metal3 ;
        RECT 3459.650 1113.000 3460.150 1113.500 ;
        RECT 3176.600 1112.950 3460.200 1113.550 ;
    END
  END t31
  PIN t32
    DIRECTION INOUT ;
    USE ANALOG ;
    PORT
      LAYER Metal5 ;
        RECT 1208.500 2433.000 1218.500 2443.000 ;
      LAYER Metal2 ;
        RECT 1191.360 2110.000 1235.640 2115.000 ;
        RECT 1212.500 2094.600 1214.500 2115.000 ;
      LAYER Metal1 ;
        RECT 1213.250 2095.350 1213.750 2095.850 ;
      LAYER Metal2 ;
        RECT 1213.250 2095.350 1213.750 2095.850 ;
      LAYER Metal1 ;
        RECT 1213.150 2095.250 3458.950 2095.950 ;
        RECT 3458.250 1114.000 3458.950 2095.950 ;
        RECT 3458.350 1114.100 3458.850 1114.600 ;
      LAYER Metal2 ;
        RECT 3458.350 1114.100 3458.850 1114.600 ;
        RECT 3458.350 1114.100 3458.850 1114.600 ;
      LAYER Metal3 ;
        RECT 3458.350 1114.100 3458.850 1114.600 ;
        RECT 3176.600 1114.050 3458.900 1114.650 ;
    END
  END t32
  PIN t33
    DIRECTION INOUT ;
    USE ANALOG ;
    PORT
      LAYER Metal5 ;
        RECT 1337.500 2433.000 1347.500 2443.000 ;
      LAYER Metal2 ;
        RECT 1320.360 2110.000 1364.640 2115.000 ;
        RECT 1341.500 2093.300 1343.500 2115.000 ;
      LAYER Metal1 ;
        RECT 1342.250 2094.050 1342.750 2094.550 ;
      LAYER Metal2 ;
        RECT 1342.250 2094.050 1342.750 2094.550 ;
      LAYER Metal1 ;
        RECT 1342.150 2093.950 3457.650 2094.650 ;
        RECT 3456.950 1115.100 3457.650 2094.650 ;
        RECT 3457.050 1115.200 3457.550 1115.700 ;
      LAYER Metal2 ;
        RECT 3457.050 1115.200 3457.550 1115.700 ;
        RECT 3457.050 1115.200 3457.550 1115.700 ;
      LAYER Metal3 ;
        RECT 3457.050 1115.200 3457.550 1115.700 ;
        RECT 3176.600 1115.150 3457.600 1115.750 ;
    END
  END t33
  PIN t34
    DIRECTION INOUT ;
    USE ANALOG ;
    PORT
      LAYER Metal5 ;
        RECT 1466.500 2433.000 1476.500 2443.000 ;
      LAYER Metal2 ;
        RECT 1449.360 2110.000 1493.640 2115.000 ;
        RECT 1470.500 2092.000 1472.500 2115.000 ;
      LAYER Metal1 ;
        RECT 1471.250 2092.750 1471.750 2093.250 ;
      LAYER Metal2 ;
        RECT 1471.250 2092.750 1471.750 2093.250 ;
      LAYER Metal1 ;
        RECT 1471.150 2092.650 3456.350 2093.350 ;
        RECT 3455.650 1116.200 3456.350 2093.350 ;
        RECT 3455.750 1116.300 3456.250 1116.800 ;
      LAYER Metal2 ;
        RECT 3455.750 1116.300 3456.250 1116.800 ;
        RECT 3455.750 1116.300 3456.250 1116.800 ;
      LAYER Metal3 ;
        RECT 3455.750 1116.300 3456.250 1116.800 ;
        RECT 3176.600 1116.250 3456.300 1116.850 ;
    END
  END t34
  PIN t35
    DIRECTION INOUT ;
    USE ANALOG ;
    PORT
      LAYER Metal5 ;
        RECT 1595.500 2433.000 1605.500 2443.000 ;
      LAYER Metal2 ;
        RECT 1578.360 2110.000 1622.640 2115.000 ;
        RECT 1599.500 2090.700 1601.500 2115.000 ;
      LAYER Metal1 ;
        RECT 1600.250 2091.450 1600.750 2091.950 ;
      LAYER Metal2 ;
        RECT 1600.250 2091.450 1600.750 2091.950 ;
      LAYER Metal1 ;
        RECT 1600.150 2091.350 3455.050 2092.050 ;
        RECT 3454.350 1117.300 3455.050 2092.050 ;
        RECT 3454.450 1117.400 3454.950 1117.900 ;
      LAYER Metal2 ;
        RECT 3454.450 1117.400 3454.950 1117.900 ;
        RECT 3454.450 1117.400 3454.950 1117.900 ;
      LAYER Metal3 ;
        RECT 3454.450 1117.400 3454.950 1117.900 ;
        RECT 3176.600 1117.350 3455.000 1117.950 ;
    END
  END t35
  PIN t36
    DIRECTION INOUT ;
    USE ANALOG ;
    PORT
      LAYER Metal5 ;
        RECT 1724.500 2433.000 1734.500 2443.000 ;
      LAYER Metal2 ;
        RECT 1707.360 2110.000 1751.640 2115.000 ;
        RECT 1728.500 2089.400 1730.500 2115.000 ;
      LAYER Metal1 ;
        RECT 1729.250 2090.150 1729.750 2090.650 ;
      LAYER Metal2 ;
        RECT 1729.250 2090.150 1729.750 2090.650 ;
      LAYER Metal1 ;
        RECT 1729.150 2090.050 3429.350 2090.750 ;
        RECT 3428.750 2090.150 3429.250 2090.650 ;
      LAYER Metal2 ;
        RECT 3428.750 2090.150 3429.250 2090.650 ;
        RECT 3428.650 1822.000 3429.350 2090.750 ;
        RECT 3428.750 1822.100 3429.250 1822.600 ;
      LAYER Metal3 ;
        RECT 3428.750 1822.100 3429.250 1822.600 ;
        RECT 3136.600 1822.050 3429.300 1822.650 ;
    END
  END t36
  PIN t37
    DIRECTION INOUT ;
    USE ANALOG ;
    PORT
      LAYER Metal5 ;
        RECT 1853.500 2433.000 1863.500 2443.000 ;
      LAYER Metal2 ;
        RECT 1836.360 2110.000 1880.640 2115.000 ;
        RECT 1857.500 2088.100 1859.500 2115.000 ;
      LAYER Metal1 ;
        RECT 1858.250 2088.850 1858.750 2089.350 ;
      LAYER Metal2 ;
        RECT 1858.250 2088.850 1858.750 2089.350 ;
      LAYER Metal1 ;
        RECT 1858.150 2088.750 3428.050 2089.450 ;
        RECT 3427.450 2088.850 3427.950 2089.350 ;
      LAYER Metal2 ;
        RECT 3427.450 2088.850 3427.950 2089.350 ;
        RECT 3427.350 1823.100 3428.050 2089.450 ;
        RECT 3427.450 1823.200 3427.950 1823.700 ;
      LAYER Metal3 ;
        RECT 3427.450 1823.200 3427.950 1823.700 ;
        RECT 3136.600 1823.150 3428.000 1823.750 ;
    END
  END t37
  PIN t38
    DIRECTION INOUT ;
    USE ANALOG ;
    PORT
      LAYER Metal5 ;
        RECT 1982.500 2433.000 1992.500 2443.000 ;
      LAYER Metal2 ;
        RECT 1965.360 2110.000 2009.640 2115.000 ;
        RECT 1986.500 2086.800 1988.500 2115.000 ;
      LAYER Metal1 ;
        RECT 1987.250 2087.550 1987.750 2088.050 ;
      LAYER Metal2 ;
        RECT 1987.250 2087.550 1987.750 2088.050 ;
      LAYER Metal1 ;
        RECT 1987.150 2087.450 3426.750 2088.150 ;
        RECT 3426.150 2087.550 3426.650 2088.050 ;
      LAYER Metal2 ;
        RECT 3426.150 2087.550 3426.650 2088.050 ;
        RECT 3426.050 1824.200 3426.750 2088.150 ;
        RECT 3426.150 1824.300 3426.650 1824.800 ;
      LAYER Metal3 ;
        RECT 3426.150 1824.300 3426.650 1824.800 ;
        RECT 3136.600 1824.250 3426.700 1824.850 ;
    END
  END t38
  PIN t39
    DIRECTION INOUT ;
    USE ANALOG ;
    PORT
      LAYER Metal5 ;
        RECT 2111.500 2433.000 2121.500 2443.000 ;
      LAYER Metal2 ;
        RECT 2094.360 2110.000 2138.640 2115.000 ;
        RECT 2115.500 2085.500 2117.500 2115.000 ;
      LAYER Metal1 ;
        RECT 2116.250 2086.250 2116.750 2086.750 ;
      LAYER Metal2 ;
        RECT 2116.250 2086.250 2116.750 2086.750 ;
      LAYER Metal1 ;
        RECT 2116.150 2086.150 3425.450 2086.850 ;
        RECT 3424.850 2086.250 3425.350 2086.750 ;
      LAYER Metal2 ;
        RECT 3424.850 2086.250 3425.350 2086.750 ;
        RECT 3424.750 1825.300 3425.450 2086.850 ;
        RECT 3424.850 1825.400 3425.350 1825.900 ;
      LAYER Metal3 ;
        RECT 3424.850 1825.400 3425.350 1825.900 ;
        RECT 3136.600 1825.350 3425.400 1825.950 ;
    END
  END t39
  PIN t40
    DIRECTION INOUT ;
    USE ANALOG ;
    PORT
      LAYER Metal5 ;
        RECT 2240.500 2433.000 2250.500 2443.000 ;
      LAYER Metal2 ;
        RECT 2223.360 2110.000 2267.640 2115.000 ;
        RECT 2244.500 2084.200 2246.500 2115.000 ;
      LAYER Metal1 ;
        RECT 2245.250 2084.950 2245.750 2085.450 ;
      LAYER Metal2 ;
        RECT 2245.250 2084.950 2245.750 2085.450 ;
      LAYER Metal1 ;
        RECT 2245.150 2084.850 3424.150 2085.550 ;
        RECT 3423.550 2084.950 3424.050 2085.450 ;
      LAYER Metal2 ;
        RECT 3423.550 2084.950 3424.050 2085.450 ;
        RECT 3423.450 1826.400 3424.150 2085.550 ;
        RECT 3423.550 1826.500 3424.050 1827.000 ;
      LAYER Metal3 ;
        RECT 3423.550 1826.500 3424.050 1827.000 ;
        RECT 3136.600 1826.450 3424.100 1827.050 ;
    END
  END t40
  PIN t41
    DIRECTION INOUT ;
    USE ANALOG ;
    PORT
      LAYER Metal5 ;
        RECT 2369.500 2433.000 2379.500 2443.000 ;
      LAYER Metal2 ;
        RECT 2352.360 2110.000 2396.640 2115.000 ;
        RECT 2373.500 2082.900 2375.500 2115.000 ;
      LAYER Metal1 ;
        RECT 2374.250 2083.650 2374.750 2084.150 ;
      LAYER Metal2 ;
        RECT 2374.250 2083.650 2374.750 2084.150 ;
      LAYER Metal1 ;
        RECT 2374.150 2083.550 3422.850 2084.250 ;
        RECT 3422.250 2083.650 3422.750 2084.150 ;
      LAYER Metal2 ;
        RECT 3422.250 2083.650 3422.750 2084.150 ;
        RECT 3422.150 1827.500 3422.850 2084.250 ;
        RECT 3422.250 1827.600 3422.750 1828.100 ;
      LAYER Metal3 ;
        RECT 3422.250 1827.600 3422.750 1828.100 ;
        RECT 3136.600 1827.550 3422.800 1828.150 ;
    END
  END t41
  PIN t42
    DIRECTION INOUT ;
    USE ANALOG ;
    PORT
      LAYER Metal5 ;
        RECT 2498.500 2433.000 2508.500 2443.000 ;
      LAYER Metal2 ;
        RECT 2481.360 2110.000 2525.640 2115.000 ;
        RECT 2502.500 2081.600 2504.500 2115.000 ;
      LAYER Metal1 ;
        RECT 2503.250 2082.350 2503.750 2082.850 ;
      LAYER Metal2 ;
        RECT 2503.250 2082.350 2503.750 2082.850 ;
      LAYER Metal1 ;
        RECT 2503.150 2082.250 3421.550 2082.950 ;
        RECT 3420.950 2082.350 3421.450 2082.850 ;
      LAYER Metal2 ;
        RECT 3420.950 2082.350 3421.450 2082.850 ;
        RECT 3420.850 1828.600 3421.550 2082.950 ;
        RECT 3420.950 1828.700 3421.450 1829.200 ;
      LAYER Metal3 ;
        RECT 3420.950 1828.700 3421.450 1829.200 ;
        RECT 3136.600 1828.650 3421.500 1829.250 ;
    END
  END t42
  PIN t43
    DIRECTION INOUT ;
    USE ANALOG ;
    PORT
      LAYER Metal5 ;
        RECT 2627.500 2433.000 2637.500 2443.000 ;
      LAYER Metal2 ;
        RECT 2610.360 2110.000 2654.640 2115.000 ;
        RECT 2631.500 2080.300 2633.500 2115.000 ;
      LAYER Metal1 ;
        RECT 2632.250 2081.050 2632.750 2081.550 ;
      LAYER Metal2 ;
        RECT 2632.250 2081.050 2632.750 2081.550 ;
      LAYER Metal1 ;
        RECT 2632.150 2080.950 3420.250 2081.650 ;
        RECT 3419.650 2081.050 3420.150 2081.550 ;
      LAYER Metal2 ;
        RECT 3419.650 2081.050 3420.150 2081.550 ;
        RECT 3419.550 1829.700 3420.250 2081.650 ;
        RECT 3419.650 1829.800 3420.150 1830.300 ;
      LAYER Metal3 ;
        RECT 3419.650 1829.800 3420.150 1830.300 ;
        RECT 3136.600 1829.750 3420.200 1830.350 ;
    END
  END t43
  PIN t44
    DIRECTION INOUT ;
    USE ANALOG ;
    PORT
      LAYER Metal5 ;
        RECT 3014.500 2433.000 3024.500 2443.000 ;
      LAYER Metal2 ;
        RECT 2997.360 2110.000 3041.640 2115.000 ;
        RECT 3018.500 2105.000 3020.500 2115.000 ;
      LAYER Metal1 ;
        RECT 3019.250 2105.750 3019.750 2106.250 ;
      LAYER Metal2 ;
        RECT 3019.250 2105.750 3019.750 2106.250 ;
      LAYER Metal1 ;
        RECT 3019.150 2105.650 3479.750 2106.350 ;
        RECT 3479.050 1474.700 3479.750 2106.350 ;
        RECT 3479.150 1474.800 3479.650 1475.300 ;
      LAYER Metal2 ;
        RECT 3479.150 1474.800 3479.650 1475.300 ;
        RECT 3479.150 1474.800 3479.650 1475.300 ;
      LAYER Metal3 ;
        RECT 3479.150 1474.800 3479.650 1475.300 ;
        RECT 3236.600 1474.750 3479.700 1475.350 ;
    END
  END t44
  PIN t45
    DIRECTION INOUT ;
    USE ANALOG ;
    PORT
      LAYER Metal5 ;
        RECT 3143.500 2433.000 3153.500 2443.000 ;
      LAYER Metal2 ;
        RECT 3126.360 2110.000 3170.640 2115.000 ;
        RECT 3147.500 2103.700 3149.500 2115.000 ;
      LAYER Metal1 ;
        RECT 3148.250 2104.450 3148.750 2104.950 ;
      LAYER Metal2 ;
        RECT 3148.250 2104.450 3148.750 2104.950 ;
      LAYER Metal1 ;
        RECT 3148.150 2104.350 3478.450 2105.050 ;
        RECT 3477.750 1473.600 3478.450 2105.050 ;
        RECT 3477.850 1473.700 3478.350 1474.200 ;
      LAYER Metal2 ;
        RECT 3477.850 1473.700 3478.350 1474.200 ;
        RECT 3477.850 1473.700 3478.350 1474.200 ;
      LAYER Metal3 ;
        RECT 3477.850 1473.700 3478.350 1474.200 ;
        RECT 3236.600 1473.650 3478.400 1474.250 ;
    END
  END t45
  PIN t46
    DIRECTION INOUT ;
    USE ANALOG ;
    PORT
      LAYER Metal5 ;
        RECT 3272.500 2433.000 3282.500 2443.000 ;
      LAYER Metal2 ;
        RECT 3255.360 2110.000 3299.640 2115.000 ;
        RECT 3276.500 2102.400 3278.500 2115.000 ;
      LAYER Metal1 ;
        RECT 3277.250 2103.150 3277.750 2103.650 ;
      LAYER Metal2 ;
        RECT 3277.250 2103.150 3277.750 2103.650 ;
      LAYER Metal1 ;
        RECT 3277.150 2103.050 3477.150 2103.750 ;
        RECT 3476.450 1472.500 3477.150 2103.750 ;
        RECT 3476.550 1472.600 3477.050 1473.100 ;
      LAYER Metal2 ;
        RECT 3476.550 1472.600 3477.050 1473.100 ;
        RECT 3476.550 1472.600 3477.050 1473.100 ;
      LAYER Metal3 ;
        RECT 3476.550 1472.600 3477.050 1473.100 ;
        RECT 3236.600 1472.550 3477.100 1473.150 ;
    END
  END t46
  PIN t47
    DIRECTION INOUT ;
    USE ANALOG ;
    PORT
      LAYER Metal5 ;
        RECT 3401.500 2433.000 3411.500 2443.000 ;
      LAYER Metal2 ;
        RECT 3384.360 2110.000 3428.640 2115.000 ;
        RECT 3405.500 2101.100 3407.500 2115.000 ;
      LAYER Metal1 ;
        RECT 3406.250 2101.850 3406.750 2102.350 ;
      LAYER Metal2 ;
        RECT 3406.250 2101.850 3406.750 2102.350 ;
      LAYER Metal1 ;
        RECT 3406.150 2101.750 3475.850 2102.450 ;
        RECT 3475.150 1471.400 3475.850 2102.450 ;
        RECT 3475.250 1471.500 3475.750 1472.000 ;
      LAYER Metal2 ;
        RECT 3475.250 1471.500 3475.750 1472.000 ;
        RECT 3475.250 1471.500 3475.750 1472.000 ;
      LAYER Metal3 ;
        RECT 3475.250 1471.500 3475.750 1472.000 ;
        RECT 3236.600 1471.450 3475.800 1472.050 ;
    END
  END t47
  OBS
      LAYER Metal1 ;
        RECT 338.700 727.200 342.300 730.800 ;
        RECT 338.500 338.500 342.500 1567.350 ;
        RECT 338.500 338.500 3507.500 342.500 ;
        RECT 3503.500 338.500 3507.500 1815.250 ;
        RECT 338.700 1082.750 342.300 1086.350 ;
        RECT 338.700 1563.550 342.300 1567.150 ;
        RECT 3503.700 649.750 3507.300 653.350 ;
        RECT 3503.700 1099.050 3507.300 1102.650 ;
        RECT 3503.700 1456.450 3507.300 1460.050 ;
        RECT 3503.700 1811.450 3507.300 1815.050 ;
        RECT 343.400 868.200 347.000 871.800 ;
        RECT 343.200 343.200 347.200 1572.350 ;
        RECT 343.200 343.200 3502.800 347.200 ;
        RECT 3498.800 343.200 3502.800 1805.000 ;
        RECT 343.400 1087.750 347.000 1091.350 ;
        RECT 343.400 1568.550 347.000 1572.150 ;
        RECT 3499.000 654.750 3502.600 658.350 ;
        RECT 3499.000 1104.050 3502.600 1107.650 ;
        RECT 3499.000 1461.450 3502.600 1465.050 ;
        RECT 3499.000 1801.200 3502.600 1804.800 ;
        RECT 350.750 1010.750 351.250 1011.250 ;
        RECT 350.650 1010.650 351.350 1094.000 ;
        RECT 350.750 1093.400 351.250 1093.900 ;
        RECT 352.050 1151.750 352.550 1152.250 ;
        RECT 351.950 1094.400 352.650 1152.350 ;
        RECT 352.050 1094.500 352.550 1095.000 ;
        RECT 353.350 1292.750 353.850 1293.250 ;
        RECT 353.250 1095.500 353.950 1293.350 ;
        RECT 353.350 1095.600 353.850 1096.100 ;
        RECT 354.650 1433.750 355.150 1434.250 ;
        RECT 354.550 1096.600 355.250 1434.350 ;
        RECT 354.650 1096.700 355.150 1097.200 ;
        RECT 357.250 1715.750 357.750 1716.250 ;
        RECT 357.150 1575.200 357.850 1716.350 ;
        RECT 357.250 1575.300 357.750 1575.800 ;
        RECT 1471.250 350.750 1471.750 351.250 ;
        RECT 358.450 350.650 1471.850 351.350 ;
        RECT 358.450 350.650 359.150 1098.400 ;
        RECT 358.550 1097.800 359.050 1098.300 ;
        RECT 1600.250 352.050 1600.750 352.550 ;
        RECT 359.750 351.950 1600.850 352.650 ;
        RECT 359.750 351.950 360.450 1099.500 ;
        RECT 359.850 1098.900 360.350 1099.400 ;
        RECT 1729.250 353.350 1729.750 353.850 ;
        RECT 361.050 353.250 1729.850 353.950 ;
        RECT 361.050 353.250 361.750 1100.600 ;
        RECT 361.150 1100.000 361.650 1100.500 ;
        RECT 1858.250 354.650 1858.750 355.150 ;
        RECT 362.350 354.550 1858.850 355.250 ;
        RECT 362.350 354.550 363.050 1101.700 ;
        RECT 362.450 1101.100 362.950 1101.600 ;
        RECT 1987.250 355.950 1987.750 356.450 ;
        RECT 363.650 355.850 1987.850 356.550 ;
        RECT 363.650 355.850 364.350 1577.000 ;
        RECT 363.750 1576.400 364.250 1576.900 ;
        RECT 2116.250 357.250 2116.750 357.750 ;
        RECT 364.950 357.150 2116.850 357.850 ;
        RECT 364.950 357.150 365.650 1578.100 ;
        RECT 365.050 1577.500 365.550 1578.000 ;
        RECT 2245.250 358.550 2245.750 359.050 ;
        RECT 366.250 358.450 2245.850 359.150 ;
        RECT 366.250 358.450 366.950 1579.200 ;
        RECT 366.350 1578.600 366.850 1579.100 ;
        RECT 2374.250 359.850 2374.750 360.350 ;
        RECT 367.550 359.750 2374.850 360.450 ;
        RECT 367.550 359.750 368.250 1580.300 ;
        RECT 367.650 1579.700 368.150 1580.200 ;
        RECT 2503.250 361.150 2503.750 361.650 ;
        RECT 368.850 361.050 2503.850 361.750 ;
        RECT 368.850 361.050 369.550 1581.400 ;
        RECT 368.950 1580.800 369.450 1581.300 ;
        RECT 2632.250 362.450 2632.750 362.950 ;
        RECT 370.150 362.350 2632.850 363.050 ;
        RECT 370.150 362.350 370.850 1582.500 ;
        RECT 370.250 1581.900 370.750 1582.400 ;
        RECT 3019.250 363.750 3019.750 364.250 ;
        RECT 3019.150 363.650 3495.350 364.350 ;
        RECT 3494.650 363.650 3495.350 661.000 ;
        RECT 3494.750 660.400 3495.250 660.900 ;
        RECT 3148.250 365.050 3148.750 365.550 ;
        RECT 3148.150 364.950 3494.050 365.650 ;
        RECT 3493.350 364.950 3494.050 662.100 ;
        RECT 3493.450 661.500 3493.950 662.000 ;
        RECT 3277.250 366.350 3277.750 366.850 ;
        RECT 3277.150 366.250 3492.750 366.950 ;
        RECT 3492.050 366.250 3492.750 663.200 ;
        RECT 3492.150 662.600 3492.650 663.100 ;
        RECT 3406.250 367.650 3406.750 368.150 ;
        RECT 3406.150 367.550 3491.450 368.250 ;
        RECT 3490.750 367.550 3491.450 664.300 ;
        RECT 3490.850 663.700 3491.350 664.200 ;
        RECT 3489.550 728.750 3490.050 729.250 ;
        RECT 3489.450 664.700 3490.150 729.350 ;
        RECT 3489.550 664.800 3490.050 665.300 ;
        RECT 3488.250 869.750 3488.750 870.250 ;
        RECT 3488.150 665.800 3488.850 870.350 ;
        RECT 3488.250 665.900 3488.750 666.400 ;
        RECT 3486.950 1010.750 3487.450 1011.250 ;
        RECT 3486.850 666.900 3487.550 1011.350 ;
        RECT 3486.950 667.000 3487.450 667.500 ;
        RECT 3485.650 1151.750 3486.150 1152.250 ;
        RECT 3485.550 668.000 3486.250 1152.350 ;
        RECT 3485.650 668.100 3486.150 668.600 ;
        RECT 3484.350 1292.750 3484.850 1293.250 ;
        RECT 3484.250 1292.650 3484.950 1467.700 ;
        RECT 3484.350 1467.100 3484.850 1467.600 ;
        RECT 3483.050 1433.750 3483.550 1434.250 ;
        RECT 3482.950 1433.650 3483.650 1468.800 ;
        RECT 3483.050 1468.200 3483.550 1468.700 ;
        RECT 3481.750 1574.750 3482.250 1575.250 ;
        RECT 3481.650 1469.200 3482.350 1575.350 ;
        RECT 3481.750 1469.300 3482.250 1469.800 ;
        RECT 3480.450 1715.750 3480.950 1716.250 ;
        RECT 3480.350 1470.300 3481.050 1716.350 ;
        RECT 3480.450 1470.400 3480.950 1470.900 ;
        RECT 439.250 2100.550 439.750 2101.050 ;
        RECT 439.150 2100.450 3464.150 2101.150 ;
        RECT 3463.450 1109.600 3464.150 2101.150 ;
        RECT 3463.550 1109.700 3464.050 1110.200 ;
        RECT 568.250 2099.250 568.750 2099.750 ;
        RECT 568.150 2099.150 3462.850 2099.850 ;
        RECT 3462.150 1110.700 3462.850 2099.850 ;
        RECT 3462.250 1110.800 3462.750 1111.300 ;
        RECT 697.250 2097.950 697.750 2098.450 ;
        RECT 697.150 2097.850 3461.550 2098.550 ;
        RECT 3460.850 1111.800 3461.550 2098.550 ;
        RECT 3460.950 1111.900 3461.450 1112.400 ;
        RECT 826.250 2096.650 826.750 2097.150 ;
        RECT 826.150 2096.550 3460.250 2097.250 ;
        RECT 3459.550 1112.900 3460.250 2097.250 ;
        RECT 3459.650 1113.000 3460.150 1113.500 ;
        RECT 1213.250 2095.350 1213.750 2095.850 ;
        RECT 1213.150 2095.250 3458.950 2095.950 ;
        RECT 3458.250 1114.000 3458.950 2095.950 ;
        RECT 3458.350 1114.100 3458.850 1114.600 ;
        RECT 1342.250 2094.050 1342.750 2094.550 ;
        RECT 1342.150 2093.950 3457.650 2094.650 ;
        RECT 3456.950 1115.100 3457.650 2094.650 ;
        RECT 3457.050 1115.200 3457.550 1115.700 ;
        RECT 1471.250 2092.750 1471.750 2093.250 ;
        RECT 1471.150 2092.650 3456.350 2093.350 ;
        RECT 3455.650 1116.200 3456.350 2093.350 ;
        RECT 3455.750 1116.300 3456.250 1116.800 ;
        RECT 1600.250 2091.450 1600.750 2091.950 ;
        RECT 1600.150 2091.350 3455.050 2092.050 ;
        RECT 3454.350 1117.300 3455.050 2092.050 ;
        RECT 3454.450 1117.400 3454.950 1117.900 ;
        RECT 1729.250 2090.150 1729.750 2090.650 ;
        RECT 1729.150 2090.050 3429.350 2090.750 ;
        RECT 3428.750 2090.150 3429.250 2090.650 ;
        RECT 1858.250 2088.850 1858.750 2089.350 ;
        RECT 1858.150 2088.750 3428.050 2089.450 ;
        RECT 3427.450 2088.850 3427.950 2089.350 ;
        RECT 1987.250 2087.550 1987.750 2088.050 ;
        RECT 1987.150 2087.450 3426.750 2088.150 ;
        RECT 3426.150 2087.550 3426.650 2088.050 ;
        RECT 2116.250 2086.250 2116.750 2086.750 ;
        RECT 2116.150 2086.150 3425.450 2086.850 ;
        RECT 3424.850 2086.250 3425.350 2086.750 ;
        RECT 2245.250 2084.950 2245.750 2085.450 ;
        RECT 2245.150 2084.850 3424.150 2085.550 ;
        RECT 3423.550 2084.950 3424.050 2085.450 ;
        RECT 2374.250 2083.650 2374.750 2084.150 ;
        RECT 2374.150 2083.550 3422.850 2084.250 ;
        RECT 3422.250 2083.650 3422.750 2084.150 ;
        RECT 2503.250 2082.350 2503.750 2082.850 ;
        RECT 2503.150 2082.250 3421.550 2082.950 ;
        RECT 3420.950 2082.350 3421.450 2082.850 ;
        RECT 2632.250 2081.050 2632.750 2081.550 ;
        RECT 2632.150 2080.950 3420.250 2081.650 ;
        RECT 3419.650 2081.050 3420.150 2081.550 ;
        RECT 3019.250 2105.750 3019.750 2106.250 ;
        RECT 3019.150 2105.650 3479.750 2106.350 ;
        RECT 3479.050 1474.700 3479.750 2106.350 ;
        RECT 3479.150 1474.800 3479.650 1475.300 ;
        RECT 3148.250 2104.450 3148.750 2104.950 ;
        RECT 3148.150 2104.350 3478.450 2105.050 ;
        RECT 3477.750 1473.600 3478.450 2105.050 ;
        RECT 3477.850 1473.700 3478.350 1474.200 ;
        RECT 3277.250 2103.150 3277.750 2103.650 ;
        RECT 3277.150 2103.050 3477.150 2103.750 ;
        RECT 3476.450 1472.500 3477.150 2103.750 ;
        RECT 3476.550 1472.600 3477.050 1473.100 ;
        RECT 3406.250 2101.850 3406.750 2102.350 ;
        RECT 3406.150 2101.750 3475.850 2102.450 ;
        RECT 3475.150 1471.400 3475.850 2102.450 ;
        RECT 3475.250 1471.500 3475.750 1472.000 ;
      LAYER Metal2 ;
        RECT 330.000 706.860 335.000 751.140 ;
        RECT 331.730 728.130 333.470 729.870 ;
        RECT 331.000 728.000 334.000 730.000 ;
        RECT 338.700 727.200 342.300 730.800 ;
        RECT 338.700 727.200 342.300 730.800 ;
        RECT 632.300 1082.750 635.900 1086.350 ;
        RECT 634.100 1082.550 637.100 1086.550 ;
        RECT 712.300 1563.550 715.900 1567.150 ;
        RECT 714.100 1563.350 717.100 1567.350 ;
        RECT 3228.100 649.750 3231.700 653.350 ;
        RECT 3226.900 649.550 3229.900 653.550 ;
        RECT 3178.100 1099.050 3181.700 1102.650 ;
        RECT 3176.900 1098.850 3179.900 1102.850 ;
        RECT 3238.100 1456.450 3241.700 1460.050 ;
        RECT 3236.900 1456.250 3239.900 1460.250 ;
        RECT 3138.100 1811.450 3141.700 1815.050 ;
        RECT 3136.900 1811.250 3139.900 1815.250 ;
        RECT 338.700 1082.750 342.300 1086.350 ;
        RECT 338.700 1082.750 342.300 1086.350 ;
        RECT 338.700 1563.550 342.300 1567.150 ;
        RECT 338.700 1563.550 342.300 1567.150 ;
        RECT 3503.700 649.750 3507.300 653.350 ;
        RECT 3503.700 649.750 3507.300 653.350 ;
        RECT 3503.700 1099.050 3507.300 1102.650 ;
        RECT 3503.700 1099.050 3507.300 1102.650 ;
        RECT 3503.700 1456.450 3507.300 1460.050 ;
        RECT 3503.700 1456.450 3507.300 1460.050 ;
        RECT 3503.700 1811.450 3507.300 1815.050 ;
        RECT 3503.700 1811.450 3507.300 1815.050 ;
        RECT 330.000 847.860 335.000 892.140 ;
        RECT 331.730 869.130 333.470 870.870 ;
        RECT 331.000 869.000 334.000 871.000 ;
        RECT 343.400 868.200 347.000 871.800 ;
        RECT 343.400 868.200 347.000 871.800 ;
        RECT 632.300 1087.750 635.900 1091.350 ;
        RECT 634.100 1087.550 637.100 1091.550 ;
        RECT 712.300 1568.550 715.900 1572.150 ;
        RECT 714.100 1568.350 717.100 1572.350 ;
        RECT 3228.100 654.750 3231.700 658.350 ;
        RECT 3226.900 654.550 3229.900 658.550 ;
        RECT 3178.100 1104.050 3181.700 1107.650 ;
        RECT 3176.900 1103.850 3179.900 1107.850 ;
        RECT 3238.100 1461.450 3241.700 1465.050 ;
        RECT 3236.900 1461.250 3239.900 1465.250 ;
        RECT 3432.200 1801.200 3435.800 1804.800 ;
        RECT 3432.000 1801.000 3436.000 1820.250 ;
        RECT 3432.200 1816.450 3435.800 1820.050 ;
        RECT 3138.100 1816.450 3141.700 1820.050 ;
        RECT 3136.900 1816.250 3139.900 1820.250 ;
        RECT 343.400 1087.750 347.000 1091.350 ;
        RECT 343.400 1087.750 347.000 1091.350 ;
        RECT 343.400 1568.550 347.000 1572.150 ;
        RECT 343.400 1568.550 347.000 1572.150 ;
        RECT 3499.000 654.750 3502.600 658.350 ;
        RECT 3499.000 654.750 3502.600 658.350 ;
        RECT 3499.000 1104.050 3502.600 1107.650 ;
        RECT 3499.000 1104.050 3502.600 1107.650 ;
        RECT 3499.000 1461.450 3502.600 1465.050 ;
        RECT 3499.000 1461.450 3502.600 1465.050 ;
        RECT 3499.000 1801.200 3502.600 1804.800 ;
        RECT 3499.000 1801.200 3502.600 1804.800 ;
        RECT 330.000 988.860 335.000 1033.140 ;
        RECT 331.730 1010.130 333.470 1011.870 ;
        RECT 331.000 1010.000 334.000 1012.000 ;
        RECT 350.750 1010.750 351.250 1011.250 ;
        RECT 350.750 1010.750 351.250 1011.250 ;
        RECT 350.750 1093.400 351.250 1093.900 ;
        RECT 350.750 1093.400 351.250 1093.900 ;
        RECT 330.000 1129.860 335.000 1174.140 ;
        RECT 331.730 1151.130 333.470 1152.870 ;
        RECT 331.000 1151.000 334.000 1153.000 ;
        RECT 352.050 1151.750 352.550 1152.250 ;
        RECT 352.050 1151.750 352.550 1152.250 ;
        RECT 352.050 1094.500 352.550 1095.000 ;
        RECT 352.050 1094.500 352.550 1095.000 ;
        RECT 330.000 1270.860 335.000 1315.140 ;
        RECT 331.730 1292.130 333.470 1293.870 ;
        RECT 331.000 1292.000 334.000 1294.000 ;
        RECT 353.350 1292.750 353.850 1293.250 ;
        RECT 353.350 1292.750 353.850 1293.250 ;
        RECT 353.350 1095.600 353.850 1096.100 ;
        RECT 353.350 1095.600 353.850 1096.100 ;
        RECT 330.000 1411.860 335.000 1456.140 ;
        RECT 331.730 1433.130 333.470 1434.870 ;
        RECT 331.000 1433.000 334.000 1435.000 ;
        RECT 354.650 1433.750 355.150 1434.250 ;
        RECT 354.650 1433.750 355.150 1434.250 ;
        RECT 354.650 1096.700 355.150 1097.200 ;
        RECT 354.650 1096.700 355.150 1097.200 ;
        RECT 330.000 1552.860 335.000 1597.140 ;
        RECT 331.730 1574.130 333.470 1575.870 ;
        RECT 331.000 1574.000 334.000 1576.000 ;
        RECT 330.000 1693.860 335.000 1738.140 ;
        RECT 331.730 1715.130 333.470 1716.870 ;
        RECT 331.000 1715.000 334.000 1717.000 ;
        RECT 357.250 1715.750 357.750 1716.250 ;
        RECT 357.250 1715.750 357.750 1716.250 ;
        RECT 357.250 1575.300 357.750 1575.800 ;
        RECT 357.250 1575.300 357.750 1575.800 ;
        RECT 1449.360 330.000 1493.640 335.000 ;
        RECT 1470.500 330.000 1472.500 352.000 ;
        RECT 1471.250 350.750 1471.750 351.250 ;
        RECT 358.550 1097.800 359.050 1098.300 ;
        RECT 358.550 1097.800 359.050 1098.300 ;
        RECT 1578.360 330.000 1622.640 335.000 ;
        RECT 1599.500 330.000 1601.500 353.300 ;
        RECT 1600.250 352.050 1600.750 352.550 ;
        RECT 359.850 1098.900 360.350 1099.400 ;
        RECT 359.850 1098.900 360.350 1099.400 ;
        RECT 1707.360 330.000 1751.640 335.000 ;
        RECT 1728.500 330.000 1730.500 354.600 ;
        RECT 1729.250 353.350 1729.750 353.850 ;
        RECT 361.150 1100.000 361.650 1100.500 ;
        RECT 361.150 1100.000 361.650 1100.500 ;
        RECT 1836.360 330.000 1880.640 335.000 ;
        RECT 1857.500 330.000 1859.500 355.900 ;
        RECT 1858.250 354.650 1858.750 355.150 ;
        RECT 362.450 1101.100 362.950 1101.600 ;
        RECT 362.450 1101.100 362.950 1101.600 ;
        RECT 1965.360 330.000 2009.640 335.000 ;
        RECT 1986.500 330.000 1988.500 357.200 ;
        RECT 1987.250 355.950 1987.750 356.450 ;
        RECT 363.750 1576.400 364.250 1576.900 ;
        RECT 363.750 1576.400 364.250 1576.900 ;
        RECT 2094.360 330.000 2138.640 335.000 ;
        RECT 2115.500 330.000 2117.500 358.500 ;
        RECT 2116.250 357.250 2116.750 357.750 ;
        RECT 365.050 1577.500 365.550 1578.000 ;
        RECT 365.050 1577.500 365.550 1578.000 ;
        RECT 2223.360 330.000 2267.640 335.000 ;
        RECT 2244.500 330.000 2246.500 359.800 ;
        RECT 2245.250 358.550 2245.750 359.050 ;
        RECT 366.350 1578.600 366.850 1579.100 ;
        RECT 366.350 1578.600 366.850 1579.100 ;
        RECT 2352.360 330.000 2396.640 335.000 ;
        RECT 2373.500 330.000 2375.500 361.100 ;
        RECT 2374.250 359.850 2374.750 360.350 ;
        RECT 367.650 1579.700 368.150 1580.200 ;
        RECT 367.650 1579.700 368.150 1580.200 ;
        RECT 2481.360 330.000 2525.640 335.000 ;
        RECT 2502.500 330.000 2504.500 362.400 ;
        RECT 2503.250 361.150 2503.750 361.650 ;
        RECT 368.950 1580.800 369.450 1581.300 ;
        RECT 368.950 1580.800 369.450 1581.300 ;
        RECT 2610.360 330.000 2654.640 335.000 ;
        RECT 2631.500 330.000 2633.500 363.700 ;
        RECT 2632.250 362.450 2632.750 362.950 ;
        RECT 370.250 1581.900 370.750 1582.400 ;
        RECT 370.250 1581.900 370.750 1582.400 ;
        RECT 2997.360 330.000 3041.640 335.000 ;
        RECT 3018.500 330.000 3020.500 365.000 ;
        RECT 3019.250 363.750 3019.750 364.250 ;
        RECT 3494.750 660.400 3495.250 660.900 ;
        RECT 3494.750 660.400 3495.250 660.900 ;
        RECT 3126.360 330.000 3170.640 335.000 ;
        RECT 3147.500 330.000 3149.500 366.300 ;
        RECT 3148.250 365.050 3148.750 365.550 ;
        RECT 3493.450 661.500 3493.950 662.000 ;
        RECT 3493.450 661.500 3493.950 662.000 ;
        RECT 3255.360 330.000 3299.640 335.000 ;
        RECT 3276.500 330.000 3278.500 367.600 ;
        RECT 3277.250 366.350 3277.750 366.850 ;
        RECT 3492.150 662.600 3492.650 663.100 ;
        RECT 3492.150 662.600 3492.650 663.100 ;
        RECT 3384.360 330.000 3428.640 335.000 ;
        RECT 3405.500 330.000 3407.500 368.900 ;
        RECT 3406.250 367.650 3406.750 368.150 ;
        RECT 3490.850 663.700 3491.350 664.200 ;
        RECT 3490.850 663.700 3491.350 664.200 ;
        RECT 3511.000 706.860 3516.000 751.140 ;
        RECT 3512.530 728.130 3514.270 729.870 ;
        RECT 3512.000 728.000 3515.000 730.000 ;
        RECT 3489.550 728.750 3490.050 729.250 ;
        RECT 3489.550 728.750 3490.050 729.250 ;
        RECT 3489.550 664.800 3490.050 665.300 ;
        RECT 3489.550 664.800 3490.050 665.300 ;
        RECT 3511.000 847.860 3516.000 892.140 ;
        RECT 3512.530 869.130 3514.270 870.870 ;
        RECT 3512.000 869.000 3515.000 871.000 ;
        RECT 3488.250 869.750 3488.750 870.250 ;
        RECT 3488.250 869.750 3488.750 870.250 ;
        RECT 3488.250 665.900 3488.750 666.400 ;
        RECT 3488.250 665.900 3488.750 666.400 ;
        RECT 3511.000 988.860 3516.000 1033.140 ;
        RECT 3512.530 1010.130 3514.270 1011.870 ;
        RECT 3512.000 1010.000 3515.000 1012.000 ;
        RECT 3486.950 1010.750 3487.450 1011.250 ;
        RECT 3486.950 1010.750 3487.450 1011.250 ;
        RECT 3486.950 667.000 3487.450 667.500 ;
        RECT 3486.950 667.000 3487.450 667.500 ;
        RECT 3511.000 1129.860 3516.000 1174.140 ;
        RECT 3512.530 1151.130 3514.270 1152.870 ;
        RECT 3512.000 1151.000 3515.000 1153.000 ;
        RECT 3485.650 1151.750 3486.150 1152.250 ;
        RECT 3485.650 1151.750 3486.150 1152.250 ;
        RECT 3485.650 668.100 3486.150 668.600 ;
        RECT 3485.650 668.100 3486.150 668.600 ;
        RECT 3511.000 1270.860 3516.000 1315.140 ;
        RECT 3512.530 1292.130 3514.270 1293.870 ;
        RECT 3512.000 1292.000 3515.000 1294.000 ;
        RECT 3484.350 1292.750 3484.850 1293.250 ;
        RECT 3484.350 1292.750 3484.850 1293.250 ;
        RECT 3484.350 1467.100 3484.850 1467.600 ;
        RECT 3484.350 1467.100 3484.850 1467.600 ;
        RECT 3511.000 1411.860 3516.000 1456.140 ;
        RECT 3512.530 1433.130 3514.270 1434.870 ;
        RECT 3512.000 1433.000 3515.000 1435.000 ;
        RECT 3483.050 1433.750 3483.550 1434.250 ;
        RECT 3483.050 1433.750 3483.550 1434.250 ;
        RECT 3483.050 1468.200 3483.550 1468.700 ;
        RECT 3483.050 1468.200 3483.550 1468.700 ;
        RECT 3511.000 1552.860 3516.000 1597.140 ;
        RECT 3512.530 1574.130 3514.270 1575.870 ;
        RECT 3512.000 1574.000 3515.000 1576.000 ;
        RECT 3481.750 1574.750 3482.250 1575.250 ;
        RECT 3481.750 1574.750 3482.250 1575.250 ;
        RECT 3481.750 1469.300 3482.250 1469.800 ;
        RECT 3481.750 1469.300 3482.250 1469.800 ;
        RECT 3511.000 1693.860 3516.000 1738.140 ;
        RECT 3512.530 1715.130 3514.270 1716.870 ;
        RECT 3512.000 1715.000 3515.000 1717.000 ;
        RECT 3480.450 1715.750 3480.950 1716.250 ;
        RECT 3480.450 1715.750 3480.950 1716.250 ;
        RECT 3480.450 1470.400 3480.950 1470.900 ;
        RECT 3480.450 1470.400 3480.950 1470.900 ;
        RECT 417.360 2110.000 461.640 2115.000 ;
        RECT 438.500 2099.800 440.500 2115.000 ;
        RECT 439.250 2100.550 439.750 2101.050 ;
        RECT 3463.550 1109.700 3464.050 1110.200 ;
        RECT 3463.550 1109.700 3464.050 1110.200 ;
        RECT 546.360 2110.000 590.640 2115.000 ;
        RECT 567.500 2098.500 569.500 2115.000 ;
        RECT 568.250 2099.250 568.750 2099.750 ;
        RECT 3462.250 1110.800 3462.750 1111.300 ;
        RECT 3462.250 1110.800 3462.750 1111.300 ;
        RECT 675.360 2110.000 719.640 2115.000 ;
        RECT 696.500 2097.200 698.500 2115.000 ;
        RECT 697.250 2097.950 697.750 2098.450 ;
        RECT 3460.950 1111.900 3461.450 1112.400 ;
        RECT 3460.950 1111.900 3461.450 1112.400 ;
        RECT 804.360 2110.000 848.640 2115.000 ;
        RECT 825.500 2095.900 827.500 2115.000 ;
        RECT 826.250 2096.650 826.750 2097.150 ;
        RECT 3459.650 1113.000 3460.150 1113.500 ;
        RECT 3459.650 1113.000 3460.150 1113.500 ;
        RECT 1191.360 2110.000 1235.640 2115.000 ;
        RECT 1212.500 2094.600 1214.500 2115.000 ;
        RECT 1213.250 2095.350 1213.750 2095.850 ;
        RECT 3458.350 1114.100 3458.850 1114.600 ;
        RECT 3458.350 1114.100 3458.850 1114.600 ;
        RECT 1320.360 2110.000 1364.640 2115.000 ;
        RECT 1341.500 2093.300 1343.500 2115.000 ;
        RECT 1342.250 2094.050 1342.750 2094.550 ;
        RECT 3457.050 1115.200 3457.550 1115.700 ;
        RECT 3457.050 1115.200 3457.550 1115.700 ;
        RECT 1449.360 2110.000 1493.640 2115.000 ;
        RECT 1470.500 2092.000 1472.500 2115.000 ;
        RECT 1471.250 2092.750 1471.750 2093.250 ;
        RECT 3455.750 1116.300 3456.250 1116.800 ;
        RECT 3455.750 1116.300 3456.250 1116.800 ;
        RECT 1578.360 2110.000 1622.640 2115.000 ;
        RECT 1599.500 2090.700 1601.500 2115.000 ;
        RECT 1600.250 2091.450 1600.750 2091.950 ;
        RECT 3454.450 1117.400 3454.950 1117.900 ;
        RECT 3454.450 1117.400 3454.950 1117.900 ;
        RECT 1707.360 2110.000 1751.640 2115.000 ;
        RECT 1728.500 2089.400 1730.500 2115.000 ;
        RECT 1729.250 2090.150 1729.750 2090.650 ;
        RECT 3428.750 2090.150 3429.250 2090.650 ;
        RECT 3428.650 1822.000 3429.350 2090.750 ;
        RECT 3428.750 1822.100 3429.250 1822.600 ;
        RECT 1836.360 2110.000 1880.640 2115.000 ;
        RECT 1857.500 2088.100 1859.500 2115.000 ;
        RECT 1858.250 2088.850 1858.750 2089.350 ;
        RECT 3427.450 2088.850 3427.950 2089.350 ;
        RECT 3427.350 1823.100 3428.050 2089.450 ;
        RECT 3427.450 1823.200 3427.950 1823.700 ;
        RECT 1965.360 2110.000 2009.640 2115.000 ;
        RECT 1986.500 2086.800 1988.500 2115.000 ;
        RECT 1987.250 2087.550 1987.750 2088.050 ;
        RECT 3426.150 2087.550 3426.650 2088.050 ;
        RECT 3426.050 1824.200 3426.750 2088.150 ;
        RECT 3426.150 1824.300 3426.650 1824.800 ;
        RECT 2094.360 2110.000 2138.640 2115.000 ;
        RECT 2115.500 2085.500 2117.500 2115.000 ;
        RECT 2116.250 2086.250 2116.750 2086.750 ;
        RECT 3424.850 2086.250 3425.350 2086.750 ;
        RECT 3424.750 1825.300 3425.450 2086.850 ;
        RECT 3424.850 1825.400 3425.350 1825.900 ;
        RECT 2223.360 2110.000 2267.640 2115.000 ;
        RECT 2244.500 2084.200 2246.500 2115.000 ;
        RECT 2245.250 2084.950 2245.750 2085.450 ;
        RECT 3423.550 2084.950 3424.050 2085.450 ;
        RECT 3423.450 1826.400 3424.150 2085.550 ;
        RECT 3423.550 1826.500 3424.050 1827.000 ;
        RECT 2352.360 2110.000 2396.640 2115.000 ;
        RECT 2373.500 2082.900 2375.500 2115.000 ;
        RECT 2374.250 2083.650 2374.750 2084.150 ;
        RECT 3422.250 2083.650 3422.750 2084.150 ;
        RECT 3422.150 1827.500 3422.850 2084.250 ;
        RECT 3422.250 1827.600 3422.750 1828.100 ;
        RECT 2481.360 2110.000 2525.640 2115.000 ;
        RECT 2502.500 2081.600 2504.500 2115.000 ;
        RECT 2503.250 2082.350 2503.750 2082.850 ;
        RECT 3420.950 2082.350 3421.450 2082.850 ;
        RECT 3420.850 1828.600 3421.550 2082.950 ;
        RECT 3420.950 1828.700 3421.450 1829.200 ;
        RECT 2610.360 2110.000 2654.640 2115.000 ;
        RECT 2631.500 2080.300 2633.500 2115.000 ;
        RECT 2632.250 2081.050 2632.750 2081.550 ;
        RECT 3419.650 2081.050 3420.150 2081.550 ;
        RECT 3419.550 1829.700 3420.250 2081.650 ;
        RECT 3419.650 1829.800 3420.150 1830.300 ;
        RECT 2997.360 2110.000 3041.640 2115.000 ;
        RECT 3018.500 2105.000 3020.500 2115.000 ;
        RECT 3019.250 2105.750 3019.750 2106.250 ;
        RECT 3479.150 1474.800 3479.650 1475.300 ;
        RECT 3479.150 1474.800 3479.650 1475.300 ;
        RECT 3126.360 2110.000 3170.640 2115.000 ;
        RECT 3147.500 2103.700 3149.500 2115.000 ;
        RECT 3148.250 2104.450 3148.750 2104.950 ;
        RECT 3477.850 1473.700 3478.350 1474.200 ;
        RECT 3477.850 1473.700 3478.350 1474.200 ;
        RECT 3255.360 2110.000 3299.640 2115.000 ;
        RECT 3276.500 2102.400 3278.500 2115.000 ;
        RECT 3277.250 2103.150 3277.750 2103.650 ;
        RECT 3476.550 1472.600 3477.050 1473.100 ;
        RECT 3476.550 1472.600 3477.050 1473.100 ;
        RECT 3384.360 2110.000 3428.640 2115.000 ;
        RECT 3405.500 2101.100 3407.500 2115.000 ;
        RECT 3406.250 2101.850 3406.750 2102.350 ;
        RECT 3475.250 1471.500 3475.750 1472.000 ;
        RECT 3475.250 1471.500 3475.750 1472.000 ;
      LAYER Metal3 ;
        RECT 331.730 728.130 333.470 729.870 ;
        RECT 331.900 728.000 340.750 730.000 ;
        RECT 338.700 727.200 342.300 730.800 ;
        RECT 338.500 1082.550 636.100 1086.550 ;
        RECT 632.300 1082.750 635.900 1086.350 ;
        RECT 338.500 1563.350 716.100 1567.350 ;
        RECT 712.300 1563.550 715.900 1567.150 ;
        RECT 3227.900 649.550 3507.500 653.550 ;
        RECT 3228.100 649.750 3231.700 653.350 ;
        RECT 3177.900 1098.850 3507.500 1102.850 ;
        RECT 3178.100 1099.050 3181.700 1102.650 ;
        RECT 3237.900 1456.250 3507.500 1460.250 ;
        RECT 3238.100 1456.450 3241.700 1460.050 ;
        RECT 3137.900 1811.250 3507.500 1815.250 ;
        RECT 3138.100 1811.450 3141.700 1815.050 ;
        RECT 338.700 1082.750 342.300 1086.350 ;
        RECT 338.700 1563.550 342.300 1567.150 ;
        RECT 3503.700 649.750 3507.300 653.350 ;
        RECT 3503.700 1099.050 3507.300 1102.650 ;
        RECT 3503.700 1456.450 3507.300 1460.050 ;
        RECT 3503.700 1811.450 3507.300 1815.050 ;
        RECT 331.730 869.130 333.470 870.870 ;
        RECT 331.900 869.000 345.450 871.000 ;
        RECT 343.400 868.200 347.000 871.800 ;
        RECT 343.200 1087.550 636.100 1091.550 ;
        RECT 632.300 1087.750 635.900 1091.350 ;
        RECT 343.200 1568.350 716.100 1572.350 ;
        RECT 712.300 1568.550 715.900 1572.150 ;
        RECT 3227.900 654.550 3502.800 658.550 ;
        RECT 3228.100 654.750 3231.700 658.350 ;
        RECT 3177.900 1103.850 3502.800 1107.850 ;
        RECT 3178.100 1104.050 3181.700 1107.650 ;
        RECT 3237.900 1461.250 3502.800 1465.250 ;
        RECT 3238.100 1461.450 3241.700 1465.050 ;
        RECT 3432.000 1801.000 3502.800 1805.000 ;
        RECT 3432.200 1801.200 3435.800 1804.800 ;
        RECT 3432.200 1816.450 3435.800 1820.050 ;
        RECT 3137.900 1816.250 3436.000 1820.250 ;
        RECT 3138.100 1816.450 3141.700 1820.050 ;
        RECT 343.400 1087.750 347.000 1091.350 ;
        RECT 343.400 1568.550 347.000 1572.150 ;
        RECT 3499.000 654.750 3502.600 658.350 ;
        RECT 3499.000 1104.050 3502.600 1107.650 ;
        RECT 3499.000 1461.450 3502.600 1465.050 ;
        RECT 3499.000 1801.200 3502.600 1804.800 ;
        RECT 331.730 1010.130 333.470 1011.870 ;
        RECT 331.900 1010.000 351.250 1012.000 ;
        RECT 350.750 1010.750 351.250 1011.250 ;
        RECT 350.750 1093.400 351.250 1093.900 ;
        RECT 350.700 1093.350 637.400 1093.950 ;
        RECT 331.730 1151.130 333.470 1152.870 ;
        RECT 331.900 1151.000 352.550 1153.000 ;
        RECT 352.050 1151.750 352.550 1152.250 ;
        RECT 352.050 1094.500 352.550 1095.000 ;
        RECT 352.000 1094.450 637.400 1095.050 ;
        RECT 331.730 1292.130 333.470 1293.870 ;
        RECT 331.900 1292.000 353.850 1294.000 ;
        RECT 353.350 1292.750 353.850 1293.250 ;
        RECT 353.350 1095.600 353.850 1096.100 ;
        RECT 353.300 1095.550 637.400 1096.150 ;
        RECT 331.730 1433.130 333.470 1434.870 ;
        RECT 331.900 1433.000 355.150 1435.000 ;
        RECT 354.650 1433.750 355.150 1434.250 ;
        RECT 354.650 1096.700 355.150 1097.200 ;
        RECT 354.600 1096.650 637.400 1097.250 ;
        RECT 331.730 1574.130 333.470 1575.870 ;
        RECT 331.900 1574.000 356.450 1576.000 ;
        RECT 355.900 1574.150 717.400 1574.750 ;
        RECT 331.730 1715.130 333.470 1716.870 ;
        RECT 331.900 1715.000 357.750 1717.000 ;
        RECT 357.250 1715.750 357.750 1716.250 ;
        RECT 357.250 1575.300 357.750 1575.800 ;
        RECT 357.200 1575.250 717.400 1575.850 ;
        RECT 358.550 1097.800 359.050 1098.300 ;
        RECT 358.500 1097.750 637.400 1098.350 ;
        RECT 359.850 1098.900 360.350 1099.400 ;
        RECT 359.800 1098.850 637.400 1099.450 ;
        RECT 361.150 1100.000 361.650 1100.500 ;
        RECT 361.100 1099.950 637.400 1100.550 ;
        RECT 362.450 1101.100 362.950 1101.600 ;
        RECT 362.400 1101.050 637.400 1101.650 ;
        RECT 363.750 1576.400 364.250 1576.900 ;
        RECT 363.700 1576.350 717.400 1576.950 ;
        RECT 365.050 1577.500 365.550 1578.000 ;
        RECT 365.000 1577.450 717.400 1578.050 ;
        RECT 366.350 1578.600 366.850 1579.100 ;
        RECT 366.300 1578.550 717.400 1579.150 ;
        RECT 367.650 1579.700 368.150 1580.200 ;
        RECT 367.600 1579.650 717.400 1580.250 ;
        RECT 368.950 1580.800 369.450 1581.300 ;
        RECT 368.900 1580.750 717.400 1581.350 ;
        RECT 370.250 1581.900 370.750 1582.400 ;
        RECT 370.200 1581.850 717.400 1582.450 ;
        RECT 3494.750 660.400 3495.250 660.900 ;
        RECT 3226.600 660.350 3495.300 660.950 ;
        RECT 3493.450 661.500 3493.950 662.000 ;
        RECT 3226.600 661.450 3494.000 662.050 ;
        RECT 3492.150 662.600 3492.650 663.100 ;
        RECT 3226.600 662.550 3492.700 663.150 ;
        RECT 3490.850 663.700 3491.350 664.200 ;
        RECT 3226.600 663.650 3491.400 664.250 ;
        RECT 3512.530 728.130 3514.270 729.870 ;
        RECT 3489.550 728.000 3514.100 730.000 ;
        RECT 3489.550 728.750 3490.050 729.250 ;
        RECT 3489.550 664.800 3490.050 665.300 ;
        RECT 3226.600 664.750 3490.100 665.350 ;
        RECT 3512.530 869.130 3514.270 870.870 ;
        RECT 3488.250 869.000 3514.100 871.000 ;
        RECT 3488.250 869.750 3488.750 870.250 ;
        RECT 3488.250 665.900 3488.750 666.400 ;
        RECT 3226.600 665.850 3488.800 666.450 ;
        RECT 3512.530 1010.130 3514.270 1011.870 ;
        RECT 3486.950 1010.000 3514.100 1012.000 ;
        RECT 3486.950 1010.750 3487.450 1011.250 ;
        RECT 3486.950 667.000 3487.450 667.500 ;
        RECT 3226.600 666.950 3487.500 667.550 ;
        RECT 3512.530 1151.130 3514.270 1152.870 ;
        RECT 3485.650 1151.000 3514.100 1153.000 ;
        RECT 3485.650 1151.750 3486.150 1152.250 ;
        RECT 3485.650 668.100 3486.150 668.600 ;
        RECT 3226.600 668.050 3486.200 668.650 ;
        RECT 3512.530 1292.130 3514.270 1293.870 ;
        RECT 3484.350 1292.000 3514.100 1294.000 ;
        RECT 3484.350 1292.750 3484.850 1293.250 ;
        RECT 3484.350 1467.100 3484.850 1467.600 ;
        RECT 3236.600 1467.050 3484.900 1467.650 ;
        RECT 3512.530 1433.130 3514.270 1434.870 ;
        RECT 3483.050 1433.000 3514.100 1435.000 ;
        RECT 3483.050 1433.750 3483.550 1434.250 ;
        RECT 3483.050 1468.200 3483.550 1468.700 ;
        RECT 3236.600 1468.150 3483.600 1468.750 ;
        RECT 3512.530 1574.130 3514.270 1575.870 ;
        RECT 3481.750 1574.000 3514.100 1576.000 ;
        RECT 3481.750 1574.750 3482.250 1575.250 ;
        RECT 3481.750 1469.300 3482.250 1469.800 ;
        RECT 3236.600 1469.250 3482.300 1469.850 ;
        RECT 3512.530 1715.130 3514.270 1716.870 ;
        RECT 3480.450 1715.000 3514.100 1717.000 ;
        RECT 3480.450 1715.750 3480.950 1716.250 ;
        RECT 3480.450 1470.400 3480.950 1470.900 ;
        RECT 3236.600 1470.350 3481.000 1470.950 ;
        RECT 3463.550 1109.700 3464.050 1110.200 ;
        RECT 3176.600 1109.650 3464.100 1110.250 ;
        RECT 3462.250 1110.800 3462.750 1111.300 ;
        RECT 3176.600 1110.750 3462.800 1111.350 ;
        RECT 3460.950 1111.900 3461.450 1112.400 ;
        RECT 3176.600 1111.850 3461.500 1112.450 ;
        RECT 3459.650 1113.000 3460.150 1113.500 ;
        RECT 3176.600 1112.950 3460.200 1113.550 ;
        RECT 3458.350 1114.100 3458.850 1114.600 ;
        RECT 3176.600 1114.050 3458.900 1114.650 ;
        RECT 3457.050 1115.200 3457.550 1115.700 ;
        RECT 3176.600 1115.150 3457.600 1115.750 ;
        RECT 3455.750 1116.300 3456.250 1116.800 ;
        RECT 3176.600 1116.250 3456.300 1116.850 ;
        RECT 3454.450 1117.400 3454.950 1117.900 ;
        RECT 3176.600 1117.350 3455.000 1117.950 ;
        RECT 3428.750 1822.100 3429.250 1822.600 ;
        RECT 3136.600 1822.050 3429.300 1822.650 ;
        RECT 3427.450 1823.200 3427.950 1823.700 ;
        RECT 3136.600 1823.150 3428.000 1823.750 ;
        RECT 3426.150 1824.300 3426.650 1824.800 ;
        RECT 3136.600 1824.250 3426.700 1824.850 ;
        RECT 3424.850 1825.400 3425.350 1825.900 ;
        RECT 3136.600 1825.350 3425.400 1825.950 ;
        RECT 3423.550 1826.500 3424.050 1827.000 ;
        RECT 3136.600 1826.450 3424.100 1827.050 ;
        RECT 3422.250 1827.600 3422.750 1828.100 ;
        RECT 3136.600 1827.550 3422.800 1828.150 ;
        RECT 3420.950 1828.700 3421.450 1829.200 ;
        RECT 3136.600 1828.650 3421.500 1829.250 ;
        RECT 3419.650 1829.800 3420.150 1830.300 ;
        RECT 3136.600 1829.750 3420.200 1830.350 ;
        RECT 3479.150 1474.800 3479.650 1475.300 ;
        RECT 3236.600 1474.750 3479.700 1475.350 ;
        RECT 3477.850 1473.700 3478.350 1474.200 ;
        RECT 3236.600 1473.650 3478.400 1474.250 ;
        RECT 3476.550 1472.600 3477.050 1473.100 ;
        RECT 3236.600 1472.550 3477.100 1473.150 ;
        RECT 3475.250 1471.500 3475.750 1472.000 ;
        RECT 3236.600 1471.450 3475.800 1472.050 ;
      LAYER Metal5 ;
        RECT 2.000 724.000 12.000 734.000 ;
        RECT 2.000 865.000 12.000 875.000 ;
        RECT 2.000 1006.000 12.000 1016.000 ;
        RECT 2.000 1147.000 12.000 1157.000 ;
        RECT 2.000 1288.000 12.000 1298.000 ;
        RECT 2.000 1429.000 12.000 1439.000 ;
        RECT 2.000 1570.000 12.000 1580.000 ;
        RECT 2.000 1711.000 12.000 1721.000 ;
        RECT 1466.500 2.000 1476.500 12.000 ;
        RECT 1595.500 2.000 1605.500 12.000 ;
        RECT 1724.500 2.000 1734.500 12.000 ;
        RECT 1853.500 2.000 1863.500 12.000 ;
        RECT 1982.500 2.000 1992.500 12.000 ;
        RECT 2111.500 2.000 2121.500 12.000 ;
        RECT 2240.500 2.000 2250.500 12.000 ;
        RECT 2369.500 2.000 2379.500 12.000 ;
        RECT 2498.500 2.000 2508.500 12.000 ;
        RECT 2627.500 2.000 2637.500 12.000 ;
        RECT 3014.500 2.000 3024.500 12.000 ;
        RECT 3143.500 2.000 3153.500 12.000 ;
        RECT 3272.500 2.000 3282.500 12.000 ;
        RECT 3401.500 2.000 3411.500 12.000 ;
        RECT 3834.000 724.000 3844.000 734.000 ;
        RECT 3834.000 865.000 3844.000 875.000 ;
        RECT 3834.000 1006.000 3844.000 1016.000 ;
        RECT 3834.000 1147.000 3844.000 1157.000 ;
        RECT 3834.000 1288.000 3844.000 1298.000 ;
        RECT 3834.000 1429.000 3844.000 1439.000 ;
        RECT 3834.000 1570.000 3844.000 1580.000 ;
        RECT 3834.000 1711.000 3844.000 1721.000 ;
        RECT 434.500 2433.000 444.500 2443.000 ;
        RECT 563.500 2433.000 573.500 2443.000 ;
        RECT 692.500 2433.000 702.500 2443.000 ;
        RECT 821.500 2433.000 831.500 2443.000 ;
        RECT 1208.500 2433.000 1218.500 2443.000 ;
        RECT 1337.500 2433.000 1347.500 2443.000 ;
        RECT 1466.500 2433.000 1476.500 2443.000 ;
        RECT 1595.500 2433.000 1605.500 2443.000 ;
        RECT 1724.500 2433.000 1734.500 2443.000 ;
        RECT 1853.500 2433.000 1863.500 2443.000 ;
        RECT 1982.500 2433.000 1992.500 2443.000 ;
        RECT 2111.500 2433.000 2121.500 2443.000 ;
        RECT 2240.500 2433.000 2250.500 2443.000 ;
        RECT 2369.500 2433.000 2379.500 2443.000 ;
        RECT 2498.500 2433.000 2508.500 2443.000 ;
        RECT 2627.500 2433.000 2637.500 2443.000 ;
        RECT 3014.500 2433.000 3024.500 2443.000 ;
        RECT 3143.500 2433.000 3153.500 2443.000 ;
        RECT 3272.500 2433.000 3282.500 2443.000 ;
        RECT 3401.500 2433.000 3411.500 2443.000 ;
  END
END puf_routes
END LIBRARY
